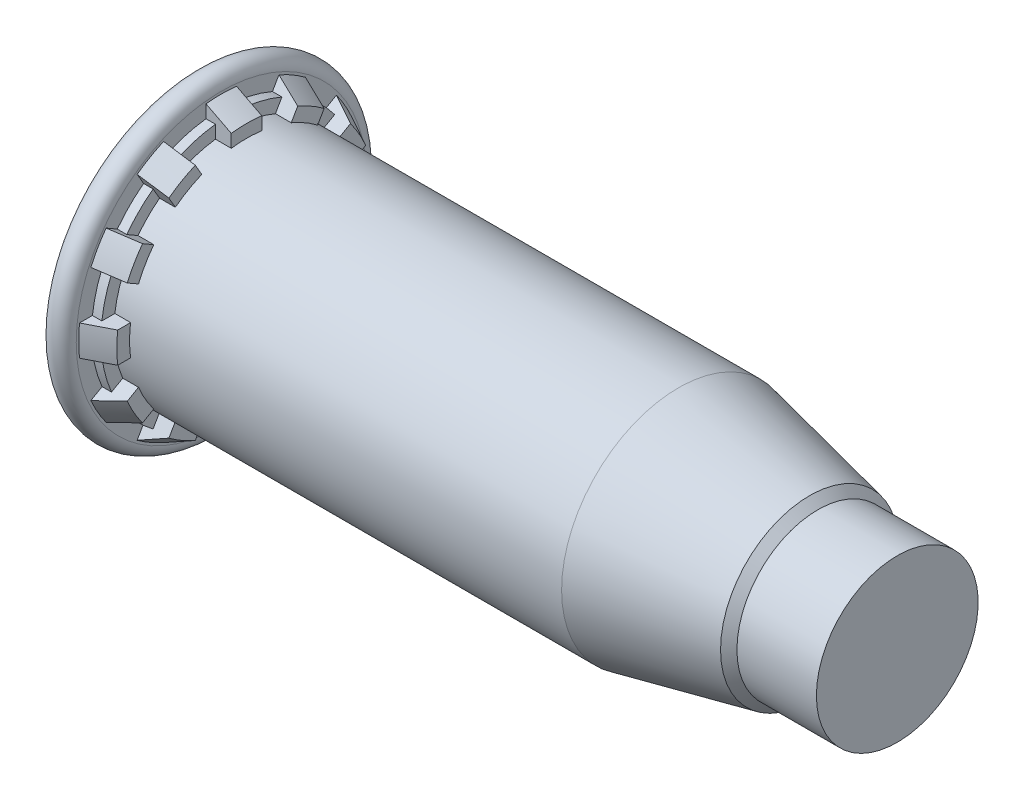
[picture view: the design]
ISO-10303-21;
HEADER;
FILE_DESCRIPTION(('STEP AP214'),'2;1');
FILE_NAME('part.step','',(''),(''),'','','');
FILE_SCHEMA(('AUTOMOTIVE_DESIGN { 1 0 10303 214 1 1 1 1 }'));
ENDSEC;
DATA;
#1=APPLICATION_CONTEXT('core data for automotive mechanical design processes');
#2=APPLICATION_PROTOCOL_DEFINITION('international standard','automotive_design',2000,#1);
#3=PRODUCT_CONTEXT('',#1,'mechanical');
#4=PRODUCT('Part','Part','',(#3));
#5=PRODUCT_RELATED_PRODUCT_CATEGORY('part','',(#4));
#6=PRODUCT_DEFINITION_FORMATION('','',#4);
#7=PRODUCT_DEFINITION_CONTEXT('part definition',#1,'design');
#8=PRODUCT_DEFINITION('design','',#6,#7);
#9=PRODUCT_DEFINITION_SHAPE('','',#8);
#10=(LENGTH_UNIT() NAMED_UNIT(*) SI_UNIT(.MILLI.,.METRE.));
#11=(NAMED_UNIT(*) PLANE_ANGLE_UNIT() SI_UNIT($,.RADIAN.));
#12=(NAMED_UNIT(*) SI_UNIT($,.STERADIAN.) SOLID_ANGLE_UNIT());
#13=UNCERTAINTY_MEASURE_WITH_UNIT(LENGTH_MEASURE(1.E-05),#10,'distance_accuracy_value','');
#14=(GEOMETRIC_REPRESENTATION_CONTEXT(3) GLOBAL_UNCERTAINTY_ASSIGNED_CONTEXT((#13)) GLOBAL_UNIT_ASSIGNED_CONTEXT((#10,
#11,#12)) REPRESENTATION_CONTEXT('',''));
#15=CARTESIAN_POINT('',(0.,0.,0.));
#16=DIRECTION('',(0.,0.,1.));
#17=DIRECTION('',(1.,0.,0.));
#18=AXIS2_PLACEMENT_3D('',#15,#16,#17);
#19=CARTESIAN_POINT('',(0.6858,0.,0.));
#20=DIRECTION('',(-1.,0.,0.));
#21=DIRECTION('',(0.,0.,1.));
#22=AXIS2_PLACEMENT_3D('',#19,#20,#21);
#23=CONICAL_SURFACE('',#22,3.8735,0.471027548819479);
#24=CARTESIAN_POINT('',(0.6858,0.,0.));
#25=DIRECTION('',(-1.,0.,0.));
#26=DIRECTION('',(0.,0.,1.));
#27=AXIS2_PLACEMENT_3D('',#24,#25,#26);
#28=CIRCLE('',#27,3.8735);
#29=CARTESIAN_POINT('',(0.6858,3.1280847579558,2.2845323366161));
#30=VERTEX_POINT('',#29);
#31=CARTESIAN_POINT('',(0.6858,3.54250541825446,1.56673469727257));
#32=VERTEX_POINT('',#31);
#33=EDGE_CURVE('E964',#30,#32,#28,.T.);
#34=ORIENTED_EDGE('',*,*,#33,.F.);
#35=CARTESIAN_POINT('',(1.3718,2.82361575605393,2.10874707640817));
#36=CARTESIAN_POINT('',(1.2288027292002,2.88712031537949,2.14541145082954));
#37=CARTESIAN_POINT('',(1.08579439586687,2.95060617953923,2.1820650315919));
#38=CARTESIAN_POINT('',(0.857053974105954,3.05211343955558,2.24067027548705));
#39=CARTESIAN_POINT('',(0.771328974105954,3.09014681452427,2.26262885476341));
#40=CARTESIAN_POINT('',(0.6856,3.12817347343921,2.28458355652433));
#41=B_SPLINE_CURVE_WITH_KNOTS('',3,(#35,#36,#37,#38,#39,#40),.UNSPECIFIED.,.F.,.F.,(4,2,4),(0.,
0.482107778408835,0.771067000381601),.UNSPECIFIED.);
#42=CARTESIAN_POINT('',(1.3716,2.82370457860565,2.10879835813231));
#43=VERTEX_POINT('',#42);
#44=EDGE_CURVE('E965',#43,#30,#41,.T.);
#45=ORIENTED_EDGE('',*,*,#44,.F.);
#46=CARTESIAN_POINT('',(1.3716,0.,0.));
#47=DIRECTION('',(-1.,0.,0.));
#48=DIRECTION('',(0.,0.,1.));
#49=AXIS2_PLACEMENT_3D('',#46,#47,#48);
#50=CIRCLE('',#49,3.52425);
#51=CARTESIAN_POINT('',(1.3716,3.23812523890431,1.39100071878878));
#52=VERTEX_POINT('',#51);
#53=EDGE_CURVE('E1233',#43,#52,#50,.T.);
#54=ORIENTED_EDGE('',*,*,#53,.T.);
#55=CARTESIAN_POINT('',(0.6856,3.54259413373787,1.5667859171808));
#56=CARTESIAN_POINT('',(0.771328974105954,3.50456747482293,1.54483121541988));
#57=CARTESIAN_POINT('',(0.857053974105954,3.46653409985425,1.52287263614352));
#58=CARTESIAN_POINT('',(1.08579439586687,3.36502683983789,1.46426739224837));
#59=CARTESIAN_POINT('',(1.2288027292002,3.30154097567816,1.42761381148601));
#60=CARTESIAN_POINT('',(1.3718,3.2380364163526,1.39094943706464));
#61=B_SPLINE_CURVE_WITH_KNOTS('',3,(#55,#56,#57,#58,#59,#60),.UNSPECIFIED.,.F.,.F.,(4,2,4),(0.,
0.288959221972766,0.771067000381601),.UNSPECIFIED.);
#62=EDGE_CURVE('E849',#32,#52,#61,.T.);
#63=ORIENTED_EDGE('',*,*,#62,.F.);
#64=EDGE_LOOP('',(#34,#45,#54,#63));
#65=FACE_BOUND('',#64,.T.);
#66=ADVANCED_FACE('F33',(#65),#23,.T.);
#67=CARTESIAN_POINT('',(0.685600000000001,2.28458355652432,3.12817347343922));
#68=CARTESIAN_POINT('',(0.771328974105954,2.2626288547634,3.09014681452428));
#69=CARTESIAN_POINT('',(0.857053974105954,2.24067027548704,3.05211343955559));
#70=CARTESIAN_POINT('',(1.08579439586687,2.18206503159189,2.95060617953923));
#71=CARTESIAN_POINT('',(1.2288027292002,2.14541145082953,2.8871203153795));
#72=CARTESIAN_POINT('',(1.3718,2.10874707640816,2.82361575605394));
#73=B_SPLINE_CURVE_WITH_KNOTS('',3,(#67,#68,#69,#70,#71,#72),.UNSPECIFIED.,.F.,.F.,(4,2,4),(0.,
0.288959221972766,0.771067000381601),.UNSPECIFIED.);
#74=CARTESIAN_POINT('',(0.6858,2.28453233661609,3.1280847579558));
#75=VERTEX_POINT('',#74);
#76=CARTESIAN_POINT('',(1.3716,2.1087983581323,2.82370457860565));
#77=VERTEX_POINT('',#76);
#78=EDGE_CURVE('E1274',#75,#77,#73,.T.);
#79=ORIENTED_EDGE('',*,*,#78,.F.);
#80=CARTESIAN_POINT('',(0.6858,1.56673469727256,3.54250541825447));
#81=VERTEX_POINT('',#80);
#82=EDGE_CURVE('E495',#81,#75,#28,.T.);
#83=ORIENTED_EDGE('',*,*,#82,.F.);
#84=CARTESIAN_POINT('',(1.3718,1.39094943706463,3.2380364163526));
#85=CARTESIAN_POINT('',(1.2288027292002,1.427613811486,3.30154097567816));
#86=CARTESIAN_POINT('',(1.08579439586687,1.46426739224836,3.3650268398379));
#87=CARTESIAN_POINT('',(0.857053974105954,1.52287263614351,3.46653409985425));
#88=CARTESIAN_POINT('',(0.771328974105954,1.54483121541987,3.50456747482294));
#89=CARTESIAN_POINT('',(0.6856,1.56678591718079,3.54259413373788));
#90=B_SPLINE_CURVE_WITH_KNOTS('',3,(#84,#85,#86,#87,#88,#89),.UNSPECIFIED.,.F.,.F.,(4,2,4),(0.,
0.482107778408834,0.7710670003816),.UNSPECIFIED.);
#91=CARTESIAN_POINT('',(1.3716,1.39100071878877,3.23812523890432));
#92=VERTEX_POINT('',#91);
#93=EDGE_CURVE('E1014',#92,#81,#90,.T.);
#94=ORIENTED_EDGE('',*,*,#93,.F.);
#95=EDGE_CURVE('E1238',#92,#77,#50,.T.);
#96=ORIENTED_EDGE('',*,*,#95,.T.);
#97=EDGE_LOOP('',(#79,#83,#94,#96));
#98=FACE_BOUND('',#97,.T.);
#99=ADVANCED_FACE('F954',(#98),#23,.T.);
#100=CARTESIAN_POINT('',(-0.377436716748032,0.414420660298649,4.39546983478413));
#101=CARTESIAN_POINT('',(-0.301617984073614,0.414420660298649,4.35668692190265));
#102=CARTESIAN_POINT('',(-0.225800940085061,0.41442066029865,4.31790070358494));
#103=CARTESIAN_POINT('',(0.339839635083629,0.414420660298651,4.02849689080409));
#104=CARTESIAN_POINT('',(0.829584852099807,0.414420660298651,3.77772613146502));
#105=CARTESIAN_POINT('',(1.56398788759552,0.414420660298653,3.40115094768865));
#106=CARTESIAN_POINT('',(1.8087531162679,0.414420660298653,3.27555603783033));
#107=CARTESIAN_POINT('',(2.29817805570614,0.414420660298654,3.02416066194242));
#108=CARTESIAN_POINT('',(2.54283776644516,0.414420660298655,2.89836019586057));
#109=CARTESIAN_POINT('',(2.78742770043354,0.414420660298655,2.77242404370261));
#110=B_SPLINE_CURVE_WITH_KNOTS('',3,(#100,#101,#102,#103,#104,#105,#106,#107,#108,#109),
.UNSPECIFIED.,.F.,.F.,(4,2,2,2,4),(0.,0.25548650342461,1.90613072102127,2.73145293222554,
3.55677535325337),.UNSPECIFIED.);
#111=CARTESIAN_POINT('',(0.6858,0.414420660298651,3.85126703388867));
#112=VERTEX_POINT('',#111);
#113=CARTESIAN_POINT('',(1.3716,0.414420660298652,3.49979907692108));
#114=VERTEX_POINT('',#113);
#115=EDGE_CURVE('E1010',#112,#114,#110,.T.);
#116=ORIENTED_EDGE('',*,*,#115,.F.);
#117=CARTESIAN_POINT('',(0.6858,-0.414420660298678,3.85126703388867));
#118=VERTEX_POINT('',#117);
#119=EDGE_CURVE('E971',#118,#112,#28,.T.);
#120=ORIENTED_EDGE('',*,*,#119,.F.);
#121=CARTESIAN_POINT('',(2.78742770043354,-0.414420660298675,2.7724240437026));
#122=CARTESIAN_POINT('',(2.54283776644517,-0.414420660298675,2.89836019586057));
#123=CARTESIAN_POINT('',(2.29817805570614,-0.414420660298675,3.02416066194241));
#124=CARTESIAN_POINT('',(1.8087531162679,-0.414420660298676,3.27555603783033));
#125=CARTESIAN_POINT('',(1.56398788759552,-0.414420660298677,3.40115094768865));
#126=CARTESIAN_POINT('',(0.829584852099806,-0.414420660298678,3.77772613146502));
#127=CARTESIAN_POINT('',(0.339839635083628,-0.414420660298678,4.02849689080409));
#128=CARTESIAN_POINT('',(-0.225800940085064,-0.41442066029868,4.31790070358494));
#129=CARTESIAN_POINT('',(-0.301617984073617,-0.41442066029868,4.35668692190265));
#130=CARTESIAN_POINT('',(-0.377436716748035,-0.41442066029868,4.39546983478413));
#131=B_SPLINE_CURVE_WITH_KNOTS('',3,(#121,#122,#123,#124,#125,#126,#127,#128,#129,#130),
.UNSPECIFIED.,.F.,.F.,(4,2,2,2,4),(0.,0.825322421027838,1.65064463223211,3.30128884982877,
3.55677535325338),.UNSPECIFIED.);
#132=CARTESIAN_POINT('',(1.3716,-0.414420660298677,3.49979907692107));
#133=VERTEX_POINT('',#132);
#134=EDGE_CURVE('E1008',#133,#118,#131,.T.);
#135=ORIENTED_EDGE('',*,*,#134,.F.);
#136=EDGE_CURVE('E1011',#133,#114,#50,.T.);
#137=ORIENTED_EDGE('',*,*,#136,.T.);
#138=EDGE_LOOP('',(#116,#120,#135,#137));
#139=FACE_BOUND('',#138,.T.);
#140=ADVANCED_FACE('F959',(#139),#23,.T.);
#141=CARTESIAN_POINT('',(0.6856,-1.56678591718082,3.54259413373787));
#142=CARTESIAN_POINT('',(0.771328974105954,-1.54483121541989,3.50456747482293));
#143=CARTESIAN_POINT('',(0.857053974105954,-1.52287263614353,3.46653409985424));
#144=CARTESIAN_POINT('',(1.08579439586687,-1.46426739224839,3.36502683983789));
#145=CARTESIAN_POINT('',(1.2288027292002,-1.42761381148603,3.30154097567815));
#146=CARTESIAN_POINT('',(1.3718,-1.39094943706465,3.2380364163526));
#147=B_SPLINE_CURVE_WITH_KNOTS('',3,(#141,#142,#143,#144,#145,#146),.UNSPECIFIED.,.F.,.F.,(4,2,
4),(0.,0.288959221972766,0.771067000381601),.UNSPECIFIED.);
#148=CARTESIAN_POINT('',(0.6858,-1.56673469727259,3.54250541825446));
#149=VERTEX_POINT('',#148);
#150=CARTESIAN_POINT('',(1.3716,-1.39100071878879,3.23812523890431));
#151=VERTEX_POINT('',#150);
#152=EDGE_CURVE('E1030',#149,#151,#147,.T.);
#153=ORIENTED_EDGE('',*,*,#152,.F.);
#154=CARTESIAN_POINT('',(0.6858,-2.28453233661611,3.12808475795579));
#155=VERTEX_POINT('',#154);
#156=EDGE_CURVE('E996',#155,#149,#28,.T.);
#157=ORIENTED_EDGE('',*,*,#156,.F.);
#158=CARTESIAN_POINT('',(1.3718,-2.10874707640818,2.82361575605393));
#159=CARTESIAN_POINT('',(1.2288027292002,-2.14541145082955,2.88712031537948));
#160=CARTESIAN_POINT('',(1.08579439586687,-2.18206503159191,2.95060617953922));
#161=CARTESIAN_POINT('',(0.857053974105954,-2.24067027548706,3.05211343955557));
#162=CARTESIAN_POINT('',(0.771328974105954,-2.26262885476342,3.09014681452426));
#163=CARTESIAN_POINT('',(0.6856,-2.28458355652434,3.1281734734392));
#164=B_SPLINE_CURVE_WITH_KNOTS('',3,(#158,#159,#160,#161,#162,#163),.UNSPECIFIED.,.F.,.F.,(4,2,
4),(0.,0.482107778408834,0.771067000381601),.UNSPECIFIED.);
#165=CARTESIAN_POINT('',(1.3716,-2.10879835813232,2.82370457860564));
#166=VERTEX_POINT('',#165);
#167=EDGE_CURVE('E1082',#166,#155,#164,.T.);
#168=ORIENTED_EDGE('',*,*,#167,.F.);
#169=EDGE_CURVE('E1346',#166,#151,#50,.T.);
#170=ORIENTED_EDGE('',*,*,#169,.T.);
#171=EDGE_LOOP('',(#153,#157,#168,#170));
#172=FACE_BOUND('',#171,.T.);
#173=ADVANCED_FACE('F1481',(#172),#23,.T.);
#174=CARTESIAN_POINT('',(0.6856,-3.12817347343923,2.28458355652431));
#175=CARTESIAN_POINT('',(0.771328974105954,-3.09014681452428,2.26262885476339));
#176=CARTESIAN_POINT('',(0.857053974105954,-3.0521134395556,2.24067027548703));
#177=CARTESIAN_POINT('',(1.08579439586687,-2.95060617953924,2.18206503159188));
#178=CARTESIAN_POINT('',(1.2288027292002,-2.88712031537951,2.14541145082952));
#179=CARTESIAN_POINT('',(1.3718,-2.82361575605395,2.10874707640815));
#180=B_SPLINE_CURVE_WITH_KNOTS('',3,(#174,#175,#176,#177,#178,#179),.UNSPECIFIED.,.F.,.F.,(4,2,
4),(0.,0.288959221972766,0.7710670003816),.UNSPECIFIED.);
#181=CARTESIAN_POINT('',(0.6858,-3.12808475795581,2.28453233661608));
#182=VERTEX_POINT('',#181);
#183=CARTESIAN_POINT('',(1.3716,-2.82370457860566,2.10879835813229));
#184=VERTEX_POINT('',#183);
#185=EDGE_CURVE('E1076',#182,#184,#180,.T.);
#186=ORIENTED_EDGE('',*,*,#185,.F.);
#187=CARTESIAN_POINT('',(0.6858,-3.54250541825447,1.56673469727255));
#188=VERTEX_POINT('',#187);
#189=EDGE_CURVE('E993',#188,#182,#28,.T.);
#190=ORIENTED_EDGE('',*,*,#189,.F.);
#191=CARTESIAN_POINT('',(1.3718,-3.23803641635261,1.39094943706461));
#192=CARTESIAN_POINT('',(1.2288027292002,-3.30154097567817,1.42761381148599));
#193=CARTESIAN_POINT('',(1.08579439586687,-3.3650268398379,1.46426739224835));
#194=CARTESIAN_POINT('',(0.857053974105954,-3.46653409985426,1.52287263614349));
#195=CARTESIAN_POINT('',(0.771328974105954,-3.50456747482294,1.54483121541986));
#196=CARTESIAN_POINT('',(0.6856,-3.54259413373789,1.56678591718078));
#197=B_SPLINE_CURVE_WITH_KNOTS('',3,(#191,#192,#193,#194,#195,#196),.UNSPECIFIED.,.F.,.F.,(4,2,
4),(0.,0.482107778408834,0.771067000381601),.UNSPECIFIED.);
#198=CARTESIAN_POINT('',(1.3716,-3.23812523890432,1.39100071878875));
#199=VERTEX_POINT('',#198);
#200=EDGE_CURVE('E1117',#199,#188,#197,.T.);
#201=ORIENTED_EDGE('',*,*,#200,.F.);
#202=EDGE_CURVE('E1341',#199,#184,#50,.T.);
#203=ORIENTED_EDGE('',*,*,#202,.T.);
#204=EDGE_LOOP('',(#186,#190,#201,#203));
#205=FACE_BOUND('',#204,.T.);
#206=ADVANCED_FACE('F1452',(#205),#23,.T.);
#207=CARTESIAN_POINT('',(-0.589165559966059,-4.50376142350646,0.414420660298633));
#208=CARTESIAN_POINT('',(-0.54848825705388,-4.48295847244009,0.414420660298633));
#209=CARTESIAN_POINT('',(-0.507811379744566,-4.46215468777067,0.414420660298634));
#210=CARTESIAN_POINT('',(0.0227243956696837,-4.19080248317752,0.414420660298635));
#211=CARTESIAN_POINT('',(0.512516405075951,-3.9401231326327,0.414420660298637));
#212=CARTESIAN_POINT('',(1.49183022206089,-3.4382371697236,0.414420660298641));
#213=CARTESIAN_POINT('',(1.98135202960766,-3.18703055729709,0.414420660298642));
#214=CARTESIAN_POINT('',(2.4706709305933,-2.93542855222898,0.414420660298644));
#215=B_SPLINE_CURVE_WITH_KNOTS('',3,(#207,#208,#209,#210,#211,#212,#213,#214),.UNSPECIFIED.,.F.,
.F.,(4,2,2,4),(0.,0.137064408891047,1.78770858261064,3.4383529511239),.UNSPECIFIED.);
#216=CARTESIAN_POINT('',(0.6858,-3.85126703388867,0.414420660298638));
#217=VERTEX_POINT('',#216);
#218=CARTESIAN_POINT('',(1.3716,-3.49979907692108,0.41442066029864));
#219=VERTEX_POINT('',#218);
#220=EDGE_CURVE('E1111',#217,#219,#215,.T.);
#221=ORIENTED_EDGE('',*,*,#220,.F.);
#222=CARTESIAN_POINT('',(0.6858,-3.85126703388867,-0.414420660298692));
#223=VERTEX_POINT('',#222);
#224=EDGE_CURVE('E990',#223,#217,#28,.T.);
#225=ORIENTED_EDGE('',*,*,#224,.F.);
#226=CARTESIAN_POINT('',(2.47067093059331,-2.93542855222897,-0.414420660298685));
#227=CARTESIAN_POINT('',(1.98135202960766,-3.18703055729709,-0.41442066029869));
#228=CARTESIAN_POINT('',(1.49183022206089,-3.4382371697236,-0.41442066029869));
#229=CARTESIAN_POINT('',(0.512516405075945,-3.9401231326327,-0.41442066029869));
#230=CARTESIAN_POINT('',(0.0227243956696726,-4.19080248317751,-0.41442066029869));
#231=CARTESIAN_POINT('',(-0.507811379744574,-4.46215468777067,-0.414420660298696));
#232=CARTESIAN_POINT('',(-0.548488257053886,-4.48295847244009,-0.414420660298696));
#233=CARTESIAN_POINT('',(-0.589165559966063,-4.50376142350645,-0.414420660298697));
#234=B_SPLINE_CURVE_WITH_KNOTS('',3,(#226,#227,#228,#229,#230,#231,#232,#233),.UNSPECIFIED.,.F.,
.F.,(4,2,2,4),(0.,1.65064436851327,3.30128854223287,3.43835295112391),.UNSPECIFIED.);
#235=CARTESIAN_POINT('',(1.3716,-3.49979907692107,-0.414420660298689));
#236=VERTEX_POINT('',#235);
#237=EDGE_CURVE('E1130',#236,#223,#234,.T.);
#238=ORIENTED_EDGE('',*,*,#237,.F.);
#239=EDGE_CURVE('E1336',#236,#219,#50,.T.);
#240=ORIENTED_EDGE('',*,*,#239,.T.);
#241=EDGE_LOOP('',(#221,#225,#238,#240));
#242=FACE_BOUND('',#241,.T.);
#243=ADVANCED_FACE('F1448',(#242),#23,.T.);
#244=CARTESIAN_POINT('',(0.6856,-3.54259413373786,-1.56678591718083));
#245=CARTESIAN_POINT('',(0.771328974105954,-3.50456747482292,-1.5448312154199));
#246=CARTESIAN_POINT('',(0.857053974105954,-3.46653409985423,-1.52287263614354));
#247=CARTESIAN_POINT('',(1.08579439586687,-3.36502683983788,-1.4642673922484));
#248=CARTESIAN_POINT('',(1.2288027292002,-3.30154097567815,-1.42761381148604));
#249=CARTESIAN_POINT('',(1.3718,-3.23803641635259,-1.39094943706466));
#250=B_SPLINE_CURVE_WITH_KNOTS('',3,(#244,#245,#246,#247,#248,#249),.UNSPECIFIED.,.F.,.F.,(4,2,
4),(0.,0.288959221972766,0.771067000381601),.UNSPECIFIED.);
#251=CARTESIAN_POINT('',(0.6858,-3.54250541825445,-1.5667346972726));
#252=VERTEX_POINT('',#251);
#253=CARTESIAN_POINT('',(1.3716,-3.2381252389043,-1.3910007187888));
#254=VERTEX_POINT('',#253);
#255=EDGE_CURVE('E1123',#252,#254,#250,.T.);
#256=ORIENTED_EDGE('',*,*,#255,.F.);
#257=CARTESIAN_POINT('',(0.6858,-3.12808475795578,-2.28453233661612));
#258=VERTEX_POINT('',#257);
#259=EDGE_CURVE('E987',#258,#252,#28,.T.);
#260=ORIENTED_EDGE('',*,*,#259,.F.);
#261=CARTESIAN_POINT('',(1.3718,-2.82361575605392,-2.10874707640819));
#262=CARTESIAN_POINT('',(1.2288027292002,-2.88712031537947,-2.14541145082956));
#263=CARTESIAN_POINT('',(1.08579439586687,-2.95060617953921,-2.18206503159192));
#264=CARTESIAN_POINT('',(0.857053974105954,-3.05211343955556,-2.24067027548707));
#265=CARTESIAN_POINT('',(0.771328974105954,-3.09014681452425,-2.26262885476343));
#266=CARTESIAN_POINT('',(0.6856,-3.12817347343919,-2.28458355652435));
#267=B_SPLINE_CURVE_WITH_KNOTS('',3,(#261,#262,#263,#264,#265,#266),.UNSPECIFIED.,.F.,.F.,(4,2,
4),(0.,0.482107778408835,0.7710670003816),.UNSPECIFIED.);
#268=CARTESIAN_POINT('',(1.3716,-2.82370457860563,-2.10879835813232));
#269=VERTEX_POINT('',#268);
#270=EDGE_CURVE('E1165',#269,#258,#267,.T.);
#271=ORIENTED_EDGE('',*,*,#270,.F.);
#272=EDGE_CURVE('E1331',#269,#254,#50,.T.);
#273=ORIENTED_EDGE('',*,*,#272,.T.);
#274=EDGE_LOOP('',(#256,#260,#271,#273));
#275=FACE_BOUND('',#274,.T.);
#276=ADVANCED_FACE('F1444',(#275),#23,.T.);
#277=CARTESIAN_POINT('',(0.6856,-2.2845835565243,-3.12817347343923));
#278=CARTESIAN_POINT('',(0.771328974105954,-2.26262885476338,-3.09014681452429));
#279=CARTESIAN_POINT('',(0.857053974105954,-2.24067027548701,-3.0521134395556));
#280=CARTESIAN_POINT('',(1.08579439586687,-2.18206503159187,-2.95060617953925));
#281=CARTESIAN_POINT('',(1.2288027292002,-2.14541145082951,-2.88712031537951));
#282=CARTESIAN_POINT('',(1.3718,-2.10874707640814,-2.82361575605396));
#283=B_SPLINE_CURVE_WITH_KNOTS('',3,(#277,#278,#279,#280,#281,#282),.UNSPECIFIED.,.F.,.F.,(4,2,
4),(0.,0.288959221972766,0.771067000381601),.UNSPECIFIED.);
#284=CARTESIAN_POINT('',(0.6858,-2.28453233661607,-3.12808475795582));
#285=VERTEX_POINT('',#284);
#286=CARTESIAN_POINT('',(1.3716,-2.10879835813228,-2.82370457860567));
#287=VERTEX_POINT('',#286);
#288=EDGE_CURVE('E1159',#285,#287,#283,.T.);
#289=ORIENTED_EDGE('',*,*,#288,.F.);
#290=CARTESIAN_POINT('',(0.6858,-1.56673469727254,-3.54250541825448));
#291=VERTEX_POINT('',#290);
#292=EDGE_CURVE('E984',#291,#285,#28,.T.);
#293=ORIENTED_EDGE('',*,*,#292,.F.);
#294=CARTESIAN_POINT('',(1.3718,-1.3909494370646,-3.23803641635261));
#295=CARTESIAN_POINT('',(1.2288027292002,-1.42761381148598,-3.30154097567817));
#296=CARTESIAN_POINT('',(1.08579439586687,-1.46426739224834,-3.36502683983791));
#297=CARTESIAN_POINT('',(0.857053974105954,-1.52287263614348,-3.46653409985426));
#298=CARTESIAN_POINT('',(0.771328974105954,-1.54483121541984,-3.50456747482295));
#299=CARTESIAN_POINT('',(0.6856,-1.56678591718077,-3.54259413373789));
#300=B_SPLINE_CURVE_WITH_KNOTS('',3,(#294,#295,#296,#297,#298,#299),.UNSPECIFIED.,.F.,.F.,(4,2,
4),(0.,0.482107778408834,0.771067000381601),.UNSPECIFIED.);
#301=CARTESIAN_POINT('',(1.3716,-1.39100071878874,-3.23812523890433));
#302=VERTEX_POINT('',#301);
#303=EDGE_CURVE('E1178',#302,#291,#300,.T.);
#304=ORIENTED_EDGE('',*,*,#303,.F.);
#305=EDGE_CURVE('E1329',#302,#287,#50,.T.);
#306=ORIENTED_EDGE('',*,*,#305,.T.);
#307=EDGE_LOOP('',(#289,#293,#304,#306));
#308=FACE_BOUND('',#307,.T.);
#309=ADVANCED_FACE('F1425',(#308),#23,.T.);
#310=CARTESIAN_POINT('',(-0.589165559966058,-0.414420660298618,-4.50376142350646));
#311=CARTESIAN_POINT('',(-0.548488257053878,-0.414420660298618,-4.48295847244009));
#312=CARTESIAN_POINT('',(-0.507811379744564,-0.414420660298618,-4.46215468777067));
#313=CARTESIAN_POINT('',(0.0227243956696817,-0.414420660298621,-4.19080248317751));
#314=CARTESIAN_POINT('',(0.51251640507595,-0.414420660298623,-3.9401231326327));
#315=CARTESIAN_POINT('',(1.49183022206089,-0.414420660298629,-3.4382371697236));
#316=CARTESIAN_POINT('',(1.98135202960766,-0.414420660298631,-3.1870305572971));
#317=CARTESIAN_POINT('',(2.4706709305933,-0.414420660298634,-2.93542855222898));
#318=B_SPLINE_CURVE_WITH_KNOTS('',3,(#310,#311,#312,#313,#314,#315,#316,#317),.UNSPECIFIED.,.F.,
.F.,(4,2,2,4),(0.,0.137064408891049,1.78770858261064,3.43835295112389),.UNSPECIFIED.);
#319=CARTESIAN_POINT('',(0.6858,-0.414420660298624,-3.85126703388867));
#320=VERTEX_POINT('',#319);
#321=CARTESIAN_POINT('',(1.3716,-0.414420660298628,-3.49979907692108));
#322=VERTEX_POINT('',#321);
#323=EDGE_CURVE('E1171',#320,#322,#318,.T.);
#324=ORIENTED_EDGE('',*,*,#323,.F.);
#325=CARTESIAN_POINT('',(0.6858,0.414420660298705,-3.85126703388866));
#326=VERTEX_POINT('',#325);
#327=EDGE_CURVE('E981',#326,#320,#28,.T.);
#328=ORIENTED_EDGE('',*,*,#327,.F.);
#329=CARTESIAN_POINT('',(2.47067093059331,0.414420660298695,-2.93542855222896));
#330=CARTESIAN_POINT('',(1.98135202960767,0.414420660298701,-3.18703055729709));
#331=CARTESIAN_POINT('',(1.49183022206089,0.414420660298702,-3.43823716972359));
#332=CARTESIAN_POINT('',(0.512516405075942,0.414420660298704,-3.9401231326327));
#333=CARTESIAN_POINT('',(0.0227243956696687,0.414420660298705,-4.19080248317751));
#334=CARTESIAN_POINT('',(-0.507811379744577,0.414420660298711,-4.46215468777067));
#335=CARTESIAN_POINT('',(-0.548488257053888,0.414420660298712,-4.48295847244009));
#336=CARTESIAN_POINT('',(-0.589165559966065,0.414420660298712,-4.50376142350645));
#337=B_SPLINE_CURVE_WITH_KNOTS('',3,(#329,#330,#331,#332,#333,#334,#335,#336),.UNSPECIFIED.,.F.,
.F.,(4,2,2,4),(0.,1.65064436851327,3.30128854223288,3.43835295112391),.UNSPECIFIED.);
#338=CARTESIAN_POINT('',(1.3716,0.414420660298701,-3.49979907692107));
#339=VERTEX_POINT('',#338);
#340=EDGE_CURVE('E1210',#339,#326,#337,.T.);
#341=ORIENTED_EDGE('',*,*,#340,.F.);
#342=EDGE_CURVE('E1236',#339,#322,#50,.T.);
#343=ORIENTED_EDGE('',*,*,#342,.T.);
#344=EDGE_LOOP('',(#324,#328,#341,#343));
#345=FACE_BOUND('',#344,.T.);
#346=ADVANCED_FACE('F1436',(#345),#23,.T.);
#347=CARTESIAN_POINT('',(0.6856,1.56678591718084,-3.54259413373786));
#348=CARTESIAN_POINT('',(0.771328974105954,1.54483121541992,-3.50456747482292));
#349=CARTESIAN_POINT('',(0.857053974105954,1.52287263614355,-3.46653409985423));
#350=CARTESIAN_POINT('',(1.08579439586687,1.46426739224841,-3.36502683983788));
#351=CARTESIAN_POINT('',(1.2288027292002,1.42761381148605,-3.30154097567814));
#352=CARTESIAN_POINT('',(1.3718,1.39094943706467,-3.23803641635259));
#353=B_SPLINE_CURVE_WITH_KNOTS('',3,(#347,#348,#349,#350,#351,#352),.UNSPECIFIED.,.F.,.F.,(4,2,
4),(0.,0.288959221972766,0.771067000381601),.UNSPECIFIED.);
#354=CARTESIAN_POINT('',(0.6858,1.56673469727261,-3.54250541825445));
#355=VERTEX_POINT('',#354);
#356=CARTESIAN_POINT('',(1.3716,1.39100071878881,-3.2381252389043));
#357=VERTEX_POINT('',#356);
#358=EDGE_CURVE('E1205',#355,#357,#353,.T.);
#359=ORIENTED_EDGE('',*,*,#358,.F.);
#360=CARTESIAN_POINT('',(0.6858,2.28453233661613,-3.12808475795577));
#361=VERTEX_POINT('',#360);
#362=EDGE_CURVE('E973',#361,#355,#28,.T.);
#363=ORIENTED_EDGE('',*,*,#362,.F.);
#364=CARTESIAN_POINT('',(1.3718,2.1087470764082,-2.82361575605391));
#365=CARTESIAN_POINT('',(1.2288027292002,2.14541145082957,-2.88712031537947));
#366=CARTESIAN_POINT('',(1.08579439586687,2.18206503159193,-2.9506061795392));
#367=CARTESIAN_POINT('',(0.857053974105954,2.24067027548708,-3.05211343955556));
#368=CARTESIAN_POINT('',(0.771328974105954,2.26262885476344,-3.09014681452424));
#369=CARTESIAN_POINT('',(0.6856,2.28458355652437,-3.12817347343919));
#370=B_SPLINE_CURVE_WITH_KNOTS('',3,(#364,#365,#366,#367,#368,#369),.UNSPECIFIED.,.F.,.F.,(4,2,
4),(0.,0.482107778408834,0.771067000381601),.UNSPECIFIED.);
#371=CARTESIAN_POINT('',(1.3716,2.10879835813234,-2.82370457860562));
#372=VERTEX_POINT('',#371);
#373=EDGE_CURVE('E656',#372,#361,#370,.T.);
#374=ORIENTED_EDGE('',*,*,#373,.F.);
#375=EDGE_CURVE('E1232',#372,#357,#50,.T.);
#376=ORIENTED_EDGE('',*,*,#375,.T.);
#377=EDGE_LOOP('',(#359,#363,#374,#376));
#378=FACE_BOUND('',#377,.T.);
#379=ADVANCED_FACE('F1438',(#378),#23,.T.);
#380=CARTESIAN_POINT('',(0.6858,3.85126703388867,0.414420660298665));
#381=VERTEX_POINT('',#380);
#382=CARTESIAN_POINT('',(0.6858,3.85126703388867,-0.414420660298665));
#383=VERTEX_POINT('',#382);
#384=EDGE_CURVE('E968',#381,#383,#28,.T.);
#385=ORIENTED_EDGE('',*,*,#384,.F.);
#386=CARTESIAN_POINT('',(2.78742770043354,2.7724240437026,0.414420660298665));
#387=CARTESIAN_POINT('',(2.54283776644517,2.89836019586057,0.414420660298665));
#388=CARTESIAN_POINT('',(2.29817805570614,3.02416066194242,0.414420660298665));
#389=CARTESIAN_POINT('',(1.8087531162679,3.27555603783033,0.414420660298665));
#390=CARTESIAN_POINT('',(1.56398788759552,3.40115094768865,0.414420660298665));
#391=CARTESIAN_POINT('',(0.829584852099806,3.77772613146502,0.414420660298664));
#392=CARTESIAN_POINT('',(0.339839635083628,4.0284968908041,0.414420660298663));
#393=CARTESIAN_POINT('',(-0.225800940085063,4.31790070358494,0.414420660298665));
#394=CARTESIAN_POINT('',(-0.301617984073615,4.35668692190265,0.414420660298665));
#395=CARTESIAN_POINT('',(-0.377436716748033,4.39546983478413,0.414420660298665));
#396=B_SPLINE_CURVE_WITH_KNOTS('',3,(#386,#387,#388,#389,#390,#391,#392,#393,#394,#395),
.UNSPECIFIED.,.F.,.F.,(4,2,2,2,4),(0.,0.825322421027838,1.65064463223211,3.30128884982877,
3.55677535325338),.UNSPECIFIED.);
#397=CARTESIAN_POINT('',(1.3716,3.49979907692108,0.414420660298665));
#398=VERTEX_POINT('',#397);
#399=EDGE_CURVE('E858',#398,#381,#396,.T.);
#400=ORIENTED_EDGE('',*,*,#399,.F.);
#401=CARTESIAN_POINT('',(1.3716,3.49979907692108,-0.414420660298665));
#402=VERTEX_POINT('',#401);
#403=EDGE_CURVE('E1234',#398,#402,#50,.T.);
#404=ORIENTED_EDGE('',*,*,#403,.T.);
#405=CARTESIAN_POINT('',(-0.377436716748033,4.39546983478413,-0.414420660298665));
#406=CARTESIAN_POINT('',(-0.301617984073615,4.35668692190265,-0.414420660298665));
#407=CARTESIAN_POINT('',(-0.225800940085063,4.31790070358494,-0.414420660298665));
#408=CARTESIAN_POINT('',(0.339839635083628,4.0284968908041,-0.414420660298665));
#409=CARTESIAN_POINT('',(0.829584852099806,3.77772613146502,-0.414420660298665));
#410=CARTESIAN_POINT('',(1.56398788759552,3.40115094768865,-0.414420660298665));
#411=CARTESIAN_POINT('',(1.8087531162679,3.27555603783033,-0.414420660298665));
#412=CARTESIAN_POINT('',(2.29817805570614,3.02416066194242,-0.414420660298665));
#413=CARTESIAN_POINT('',(2.54283776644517,2.89836019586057,-0.414420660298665));
#414=CARTESIAN_POINT('',(2.78742770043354,2.7724240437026,-0.414420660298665));
#415=B_SPLINE_CURVE_WITH_KNOTS('',3,(#405,#406,#407,#408,#409,#410,#411,#412,#413,#414),
.UNSPECIFIED.,.F.,.F.,(4,2,2,2,4),(0.,0.255486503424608,1.90613072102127,2.73145293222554,
3.55677535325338),.UNSPECIFIED.);
#416=EDGE_CURVE('E901',#383,#402,#415,.T.);
#417=ORIENTED_EDGE('',*,*,#416,.F.);
#418=EDGE_LOOP('',(#385,#400,#404,#417));
#419=FACE_BOUND('',#418,.T.);
#420=ADVANCED_FACE('F945',(#419),#23,.T.);
#421=CARTESIAN_POINT('',(1.3716,3.52425,0.));
#422=DIRECTION('',(1.,0.,0.));
#423=DIRECTION('',(0.,0.,-1.));
#424=AXIS2_PLACEMENT_3D('',#421,#422,#423);
#425=PLANE('',#424);
#426=DIRECTION('',(0.,-0.499999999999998,-0.86602540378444));
#427=VECTOR('',#426,1.);
#428=CARTESIAN_POINT('',(1.3716,1.93281753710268,2.51889685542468));
#429=LINE('',#428,#427);
#430=CARTESIAN_POINT('',(1.3716,1.93281753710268,2.51889685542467));
#431=VERTEX_POINT('',#430);
#432=EDGE_CURVE('E647',#77,#431,#429,.T.);
#433=ORIENTED_EDGE('',*,*,#432,.F.);
#434=ORIENTED_EDGE('',*,*,#95,.F.);
#435=DIRECTION('',(0.,0.499999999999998,0.86602540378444));
#436=VECTOR('',#435,1.);
#437=CARTESIAN_POINT('',(1.3716,1.21501989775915,2.93331751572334));
#438=LINE('',#437,#436);
#439=CARTESIAN_POINT('',(1.3716,1.21501989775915,2.93331751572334));
#440=VERTEX_POINT('',#439);
#441=EDGE_CURVE('E668',#440,#92,#438,.T.);
#442=ORIENTED_EDGE('',*,*,#441,.F.);
#443=CARTESIAN_POINT('',(1.3716,0.,0.));
#444=DIRECTION('',(-1.,0.,0.));
#445=DIRECTION('',(0.,0.,1.));
#446=AXIS2_PLACEMENT_3D('',#443,#444,#445);
#447=CIRCLE('',#446,3.175);
#448=EDGE_CURVE('E1250',#440,#431,#447,.T.);
#449=ORIENTED_EDGE('',*,*,#448,.T.);
#450=EDGE_LOOP('',(#433,#434,#442,#449));
#451=FACE_BOUND('',#450,.T.);
#452=ADVANCED_FACE('F939',(#451),#425,.T.);
#453=DIRECTION('',(0.,0.,-1.));
#454=VECTOR('',#453,1.);
#455=CARTESIAN_POINT('',(1.3716,0.414420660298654,3.14783743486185));
#456=LINE('',#455,#454);
#457=CARTESIAN_POINT('',(1.3716,0.414420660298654,3.14783743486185));
#458=VERTEX_POINT('',#457);
#459=EDGE_CURVE('E662',#114,#458,#456,.T.);
#460=ORIENTED_EDGE('',*,*,#459,.F.);
#461=ORIENTED_EDGE('',*,*,#136,.F.);
#462=DIRECTION('',(0.,0.,1.));
#463=VECTOR('',#462,1.);
#464=CARTESIAN_POINT('',(1.3716,-0.414420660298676,3.14783743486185));
#465=LINE('',#464,#463);
#466=CARTESIAN_POINT('',(1.3716,-0.414420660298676,3.14783743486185));
#467=VERTEX_POINT('',#466);
#468=EDGE_CURVE('E684',#467,#133,#465,.T.);
#469=ORIENTED_EDGE('',*,*,#468,.F.);
#470=EDGE_CURVE('E1383',#467,#458,#447,.T.);
#471=ORIENTED_EDGE('',*,*,#470,.T.);
#472=EDGE_LOOP('',(#460,#461,#469,#471));
#473=FACE_BOUND('',#472,.T.);
#474=ADVANCED_FACE('F948',(#473),#425,.T.);
#475=DIRECTION('',(0.,0.500000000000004,-0.866025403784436));
#476=VECTOR('',#475,1.);
#477=CARTESIAN_POINT('',(1.3716,-1.21501989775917,2.93331751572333));
#478=LINE('',#477,#476);
#479=CARTESIAN_POINT('',(1.3716,-1.21501989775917,2.93331751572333));
#480=VERTEX_POINT('',#479);
#481=EDGE_CURVE('E678',#151,#480,#478,.T.);
#482=ORIENTED_EDGE('',*,*,#481,.F.);
#483=ORIENTED_EDGE('',*,*,#169,.F.);
#484=DIRECTION('',(0.,-0.500000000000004,0.866025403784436));
#485=VECTOR('',#484,1.);
#486=CARTESIAN_POINT('',(1.3716,-1.9328175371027,2.51889685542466));
#487=LINE('',#486,#485);
#488=CARTESIAN_POINT('',(1.3716,-1.9328175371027,2.51889685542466));
#489=VERTEX_POINT('',#488);
#490=EDGE_CURVE('E701',#489,#166,#487,.T.);
#491=ORIENTED_EDGE('',*,*,#490,.F.);
#492=EDGE_CURVE('E1385',#489,#480,#447,.T.);
#493=ORIENTED_EDGE('',*,*,#492,.T.);
#494=EDGE_LOOP('',(#482,#483,#491,#493));
#495=FACE_BOUND('',#494,.T.);
#496=ADVANCED_FACE('F1482',(#495),#425,.T.);
#497=DIRECTION('',(0.,0.866025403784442,-0.499999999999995));
#498=VECTOR('',#497,1.);
#499=CARTESIAN_POINT('',(1.3716,-2.51889685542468,1.93281753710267));
#500=LINE('',#499,#498);
#501=CARTESIAN_POINT('',(1.3716,-2.51889685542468,1.93281753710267));
#502=VERTEX_POINT('',#501);
#503=EDGE_CURVE('E695',#184,#502,#500,.T.);
#504=ORIENTED_EDGE('',*,*,#503,.F.);
#505=ORIENTED_EDGE('',*,*,#202,.F.);
#506=DIRECTION('',(0.,-0.866025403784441,0.499999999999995));
#507=VECTOR('',#506,1.);
#508=CARTESIAN_POINT('',(1.3716,-2.93331751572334,1.21501989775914));
#509=LINE('',#508,#507);
#510=CARTESIAN_POINT('',(1.3716,-2.93331751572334,1.21501989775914));
#511=VERTEX_POINT('',#510);
#512=EDGE_CURVE('E718',#511,#199,#509,.T.);
#513=ORIENTED_EDGE('',*,*,#512,.F.);
#514=EDGE_CURVE('E1389',#511,#502,#447,.T.);
#515=ORIENTED_EDGE('',*,*,#514,.T.);
#516=EDGE_LOOP('',(#504,#505,#513,#515));
#517=FACE_BOUND('',#516,.T.);
#518=ADVANCED_FACE('F1471',(#517),#425,.T.);
#519=DIRECTION('',(0.,1.,0.));
#520=VECTOR('',#519,1.);
#521=CARTESIAN_POINT('',(1.3716,-3.14783743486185,0.414420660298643));
#522=LINE('',#521,#520);
#523=CARTESIAN_POINT('',(1.3716,-3.14783743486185,0.414420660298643));
#524=VERTEX_POINT('',#523);
#525=EDGE_CURVE('E712',#219,#524,#522,.T.);
#526=ORIENTED_EDGE('',*,*,#525,.F.);
#527=ORIENTED_EDGE('',*,*,#239,.F.);
#528=DIRECTION('',(0.,-1.,0.));
#529=VECTOR('',#528,1.);
#530=CARTESIAN_POINT('',(1.3716,-3.14783743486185,-0.414420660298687));
#531=LINE('',#530,#529);
#532=CARTESIAN_POINT('',(1.3716,-3.14783743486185,-0.414420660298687));
#533=VERTEX_POINT('',#532);
#534=EDGE_CURVE('E735',#533,#236,#531,.T.);
#535=ORIENTED_EDGE('',*,*,#534,.F.);
#536=EDGE_CURVE('E1395',#533,#524,#447,.T.);
#537=ORIENTED_EDGE('',*,*,#536,.T.);
#538=EDGE_LOOP('',(#526,#527,#535,#537));
#539=FACE_BOUND('',#538,.T.);
#540=ADVANCED_FACE('F1460',(#539),#425,.T.);
#541=DIRECTION('',(0.,0.866025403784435,0.500000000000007));
#542=VECTOR('',#541,1.);
#543=CARTESIAN_POINT('',(1.3716,-2.93331751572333,-1.21501989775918));
#544=LINE('',#543,#542);
#545=CARTESIAN_POINT('',(1.3716,-2.93331751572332,-1.21501989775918));
#546=VERTEX_POINT('',#545);
#547=EDGE_CURVE('E729',#254,#546,#544,.T.);
#548=ORIENTED_EDGE('',*,*,#547,.F.);
#549=ORIENTED_EDGE('',*,*,#272,.F.);
#550=DIRECTION('',(0.,-0.866025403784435,-0.500000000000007));
#551=VECTOR('',#550,1.);
#552=CARTESIAN_POINT('',(1.3716,-2.51889685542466,-1.93281753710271));
#553=LINE('',#552,#551);
#554=CARTESIAN_POINT('',(1.3716,-2.51889685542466,-1.93281753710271));
#555=VERTEX_POINT('',#554);
#556=EDGE_CURVE('E752',#555,#269,#553,.T.);
#557=ORIENTED_EDGE('',*,*,#556,.F.);
#558=EDGE_CURVE('E1401',#555,#546,#447,.T.);
#559=ORIENTED_EDGE('',*,*,#558,.T.);
#560=EDGE_LOOP('',(#548,#549,#557,#559));
#561=FACE_BOUND('',#560,.T.);
#562=ADVANCED_FACE('F1576',(#561),#425,.T.);
#563=DIRECTION('',(0.,0.499999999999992,0.866025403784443));
#564=VECTOR('',#563,1.);
#565=CARTESIAN_POINT('',(1.3716,-1.93281753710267,-2.51889685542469));
#566=LINE('',#565,#564);
#567=CARTESIAN_POINT('',(1.3716,-1.93281753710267,-2.51889685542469));
#568=VERTEX_POINT('',#567);
#569=EDGE_CURVE('E746',#287,#568,#566,.T.);
#570=ORIENTED_EDGE('',*,*,#569,.F.);
#571=ORIENTED_EDGE('',*,*,#305,.F.);
#572=DIRECTION('',(0.,-0.499999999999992,-0.866025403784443));
#573=VECTOR('',#572,1.);
#574=CARTESIAN_POINT('',(1.3716,-1.21501989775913,-2.93331751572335));
#575=LINE('',#574,#573);
#576=CARTESIAN_POINT('',(1.3716,-1.21501989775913,-2.93331751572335));
#577=VERTEX_POINT('',#576);
#578=EDGE_CURVE('E769',#577,#302,#575,.T.);
#579=ORIENTED_EDGE('',*,*,#578,.F.);
#580=EDGE_CURVE('E1407',#577,#568,#447,.T.);
#581=ORIENTED_EDGE('',*,*,#580,.T.);
#582=EDGE_LOOP('',(#570,#571,#579,#581));
#583=FACE_BOUND('',#582,.T.);
#584=ADVANCED_FACE('F1417',(#583),#425,.T.);
#585=DIRECTION('',(0.,0.,1.));
#586=VECTOR('',#585,1.);
#587=CARTESIAN_POINT('',(1.3716,-0.414420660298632,-3.14783743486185));
#588=LINE('',#587,#586);
#589=CARTESIAN_POINT('',(1.3716,-0.414420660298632,-3.14783743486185));
#590=VERTEX_POINT('',#589);
#591=EDGE_CURVE('E763',#322,#590,#588,.T.);
#592=ORIENTED_EDGE('',*,*,#591,.F.);
#593=ORIENTED_EDGE('',*,*,#342,.F.);
#594=DIRECTION('',(0.,0.,-1.));
#595=VECTOR('',#594,1.);
#596=CARTESIAN_POINT('',(1.3716,0.414420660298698,-3.14783743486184));
#597=LINE('',#596,#595);
#598=CARTESIAN_POINT('',(1.3716,0.414420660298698,-3.14783743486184));
#599=VERTEX_POINT('',#598);
#600=EDGE_CURVE('E786',#599,#339,#597,.T.);
#601=ORIENTED_EDGE('',*,*,#600,.F.);
#602=EDGE_CURVE('E1248',#599,#590,#447,.T.);
#603=ORIENTED_EDGE('',*,*,#602,.T.);
#604=EDGE_LOOP('',(#592,#593,#601,#603));
#605=FACE_BOUND('',#604,.T.);
#606=ADVANCED_FACE('F1326',(#605),#425,.T.);
#607=DIRECTION('',(0.,-0.50000000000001,0.866025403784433));
#608=VECTOR('',#607,1.);
#609=CARTESIAN_POINT('',(1.3716,1.21501989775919,-2.93331751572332));
#610=LINE('',#609,#608);
#611=CARTESIAN_POINT('',(1.3716,1.21501989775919,-2.93331751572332));
#612=VERTEX_POINT('',#611);
#613=EDGE_CURVE('E780',#357,#612,#610,.T.);
#614=ORIENTED_EDGE('',*,*,#613,.F.);
#615=ORIENTED_EDGE('',*,*,#375,.F.);
#616=DIRECTION('',(0.,0.50000000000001,-0.866025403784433));
#617=VECTOR('',#616,1.);
#618=CARTESIAN_POINT('',(1.3716,1.93281753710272,-2.51889685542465));
#619=LINE('',#618,#617);
#620=CARTESIAN_POINT('',(1.3716,1.93281753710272,-2.51889685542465));
#621=VERTEX_POINT('',#620);
#622=EDGE_CURVE('E641',#621,#372,#619,.T.);
#623=ORIENTED_EDGE('',*,*,#622,.F.);
#624=EDGE_CURVE('E1244',#621,#612,#447,.T.);
#625=ORIENTED_EDGE('',*,*,#624,.T.);
#626=EDGE_LOOP('',(#614,#615,#623,#625));
#627=FACE_BOUND('',#626,.T.);
#628=ADVANCED_FACE('F1592',(#627),#425,.T.);
#629=DIRECTION('',(0.,-0.866025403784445,0.499999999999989));
#630=VECTOR('',#629,1.);
#631=CARTESIAN_POINT('',(1.3716,2.5188968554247,-1.93281753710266));
#632=LINE('',#631,#630);
#633=CARTESIAN_POINT('',(1.3716,2.82370457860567,-2.10879835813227));
#634=VERTEX_POINT('',#633);
#635=CARTESIAN_POINT('',(1.3716,2.5188968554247,-1.93281753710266));
#636=VERTEX_POINT('',#635);
#637=EDGE_CURVE('E797',#634,#636,#632,.T.);
#638=ORIENTED_EDGE('',*,*,#637,.F.);
#639=CARTESIAN_POINT('',(1.3716,3.23812523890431,-1.39100071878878));
#640=VERTEX_POINT('',#639);
#641=EDGE_CURVE('E972',#640,#634,#50,.T.);
#642=ORIENTED_EDGE('',*,*,#641,.F.);
#643=DIRECTION('',(0.,0.866025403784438,-0.500000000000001));
#644=VECTOR('',#643,1.);
#645=CARTESIAN_POINT('',(1.3716,2.93331751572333,-1.21501989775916));
#646=LINE('',#645,#644);
#647=CARTESIAN_POINT('',(1.3716,2.93331751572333,-1.21501989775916));
#648=VERTEX_POINT('',#647);
#649=EDGE_CURVE('E875',#648,#640,#646,.T.);
#650=ORIENTED_EDGE('',*,*,#649,.F.);
#651=EDGE_CURVE('E1230',#648,#636,#447,.T.);
#652=ORIENTED_EDGE('',*,*,#651,.T.);
#653=EDGE_LOOP('',(#638,#642,#650,#652));
#654=FACE_BOUND('',#653,.T.);
#655=ADVANCED_FACE('F951',(#654),#425,.T.);
#656=DIRECTION('',(0.,0.866025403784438,0.500000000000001));
#657=VECTOR('',#656,1.);
#658=CARTESIAN_POINT('',(1.3716,2.51889685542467,1.93281753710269));
#659=LINE('',#658,#657);
#660=CARTESIAN_POINT('',(1.3716,2.51889685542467,1.93281753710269));
#661=VERTEX_POINT('',#660);
#662=EDGE_CURVE('E652',#661,#43,#659,.T.);
#663=ORIENTED_EDGE('',*,*,#662,.F.);
#664=CARTESIAN_POINT('',(1.3716,2.93331751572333,1.21501989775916));
#665=VERTEX_POINT('',#664);
#666=EDGE_CURVE('E1245',#661,#665,#447,.T.);
#667=ORIENTED_EDGE('',*,*,#666,.T.);
#668=DIRECTION('',(0.,-0.866025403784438,-0.500000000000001));
#669=VECTOR('',#668,1.);
#670=CARTESIAN_POINT('',(1.3716,2.93331751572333,1.21501989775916));
#671=LINE('',#670,#669);
#672=EDGE_CURVE('E1273',#52,#665,#671,.T.);
#673=ORIENTED_EDGE('',*,*,#672,.F.);
#674=ORIENTED_EDGE('',*,*,#53,.F.);
#675=EDGE_LOOP('',(#663,#667,#673,#674));
#676=FACE_BOUND('',#675,.T.);
#677=ADVANCED_FACE('F940',(#676),#425,.T.);
#678=CARTESIAN_POINT('',(0.,0.,0.));
#679=DIRECTION('',(-1.,0.,0.));
#680=DIRECTION('',(0.,0.,1.));
#681=AXIS2_PLACEMENT_3D('',#678,#679,#680);
#682=PLANE('',#681);
#683=CARTESIAN_POINT('',(0.,0.,0.));
#684=DIRECTION('',(-1.,0.,0.));
#685=DIRECTION('',(0.,0.,1.));
#686=AXIS2_PLACEMENT_3D('',#683,#684,#685);
#687=CIRCLE('',#686,3.93446);
#688=CARTESIAN_POINT('',(0.,0.,3.93446));
#689=VERTEX_POINT('',#688);
#690=EDGE_CURVE('E1287',#689,#689,#687,.T.);
#691=ORIENTED_EDGE('',*,*,#690,.T.);
#692=EDGE_LOOP('',(#691));
#693=FACE_BOUND('',#692,.T.);
#694=ADVANCED_FACE('F35',(#693),#682,.T.);
#695=CARTESIAN_POINT('',(0.,0.,0.));
#696=DIRECTION('',(-1.,0.,0.));
#697=DIRECTION('',(0.,0.,1.));
#698=AXIS2_PLACEMENT_3D('',#695,#696,#697);
#699=CYLINDRICAL_SURFACE('',#698,3.93446);
#700=CARTESIAN_POINT('',(0.00507999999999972,0.,0.));
#701=DIRECTION('',(-1.,0.,0.));
#702=DIRECTION('',(0.,0.,1.));
#703=AXIS2_PLACEMENT_3D('',#700,#701,#702);
#704=CIRCLE('',#703,3.93446);
#705=CARTESIAN_POINT('',(0.00507999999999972,0.,3.93446));
#706=VERTEX_POINT('',#705);
#707=EDGE_CURVE('E1292',#706,#706,#704,.T.);
#708=ORIENTED_EDGE('',*,*,#707,.T.);
#709=EDGE_LOOP('',(#708));
#710=FACE_BOUND('',#709,.T.);
#711=ORIENTED_EDGE('',*,*,#690,.F.);
#712=EDGE_LOOP('',(#711));
#713=FACE_BOUND('',#712,.T.);
#714=ADVANCED_FACE('F1614',(#710,#713),#699,.T.);
#715=CARTESIAN_POINT('',(0.00507999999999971,3.93954,0.));
#716=DIRECTION('',(1.,0.,0.));
#717=DIRECTION('',(0.,0.,-1.));
#718=AXIS2_PLACEMENT_3D('',#715,#716,#717);
#719=PLANE('',#718);
#720=ORIENTED_EDGE('',*,*,#707,.F.);
#721=EDGE_LOOP('',(#720));
#722=FACE_BOUND('',#721,.T.);
#723=CARTESIAN_POINT('',(0.0050799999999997,0.,0.));
#724=DIRECTION('',(-1.,0.,0.));
#725=DIRECTION('',(0.,0.,1.));
#726=AXIS2_PLACEMENT_3D('',#723,#724,#725);
#727=CIRCLE('',#726,3.93954);
#728=CARTESIAN_POINT('',(0.0050799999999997,0.,3.93954));
#729=VERTEX_POINT('',#728);
#730=EDGE_CURVE('E980',#729,#729,#727,.T.);
#731=ORIENTED_EDGE('',*,*,#730,.T.);
#732=EDGE_LOOP('',(#731));
#733=FACE_BOUND('',#732,.T.);
#734=ADVANCED_FACE('F1621',(#722,#733),#719,.F.);
#735=CARTESIAN_POINT('',(0.34544,0.,0.));
#736=DIRECTION('',(-1.,0.,0.));
#737=DIRECTION('',(0.,0.,1.));
#738=AXIS2_PLACEMENT_3D('',#735,#736,#737);
#739=TOROIDAL_SURFACE('',#738,3.93954,0.34036);
#740=CARTESIAN_POINT('',(0.6858,0.,0.));
#741=DIRECTION('',(-1.,0.,0.));
#742=DIRECTION('',(0.,0.,1.));
#743=AXIS2_PLACEMENT_3D('',#740,#741,#742);
#744=CIRCLE('',#743,3.93954);
#745=CARTESIAN_POINT('',(0.6858,0.,3.93954));
#746=VERTEX_POINT('',#745);
#747=EDGE_CURVE('E977',#746,#746,#744,.T.);
#748=ORIENTED_EDGE('',*,*,#747,.T.);
#749=EDGE_LOOP('',(#748));
#750=FACE_BOUND('',#749,.T.);
#751=ORIENTED_EDGE('',*,*,#730,.F.);
#752=EDGE_LOOP('',(#751));
#753=FACE_BOUND('',#752,.T.);
#754=ADVANCED_FACE('F1628',(#750,#753),#739,.T.);
#755=CARTESIAN_POINT('',(0.6858,3.93954,0.));
#756=DIRECTION('',(1.,0.,0.));
#757=DIRECTION('',(0.,0.,-1.));
#758=AXIS2_PLACEMENT_3D('',#755,#756,#757);
#759=PLANE('',#758);
#760=ORIENTED_EDGE('',*,*,#747,.F.);
#761=EDGE_LOOP('',(#760));
#762=FACE_BOUND('',#761,.T.);
#763=ORIENTED_EDGE('',*,*,#362,.T.);
#764=DIRECTION('',(0.,-0.50000000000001,0.866025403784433));
#765=VECTOR('',#764,1.);
#766=CARTESIAN_POINT('',(0.6858,1.39100071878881,-3.2381252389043));
#767=LINE('',#766,#765);
#768=CARTESIAN_POINT('',(0.6858,1.39100071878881,-3.2381252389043));
#769=VERTEX_POINT('',#768);
#770=EDGE_CURVE('E605',#355,#769,#767,.T.);
#771=ORIENTED_EDGE('',*,*,#770,.T.);
#772=CARTESIAN_POINT('',(0.6858,0.,0.));
#773=DIRECTION('',(-1.,0.,0.));
#774=DIRECTION('',(0.,-0.866025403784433,-0.50000000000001));
#775=AXIS2_PLACEMENT_3D('',#772,#773,#774);
#776=CIRCLE('',#775,3.52425);
#777=CARTESIAN_POINT('',(0.6858,0.414420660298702,-3.49979907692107));
#778=VERTEX_POINT('',#777);
#779=EDGE_CURVE('E607',#769,#778,#776,.T.);
#780=ORIENTED_EDGE('',*,*,#779,.T.);
#781=DIRECTION('',(0.,0.,-1.));
#782=VECTOR('',#781,1.);
#783=CARTESIAN_POINT('',(0.6858,0.414420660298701,-3.49979907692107));
#784=LINE('',#783,#782);
#785=EDGE_CURVE('E611',#778,#326,#784,.T.);
#786=ORIENTED_EDGE('',*,*,#785,.T.);
#787=ORIENTED_EDGE('',*,*,#327,.T.);
#788=DIRECTION('',(0.,0.,1.));
#789=VECTOR('',#788,1.);
#790=CARTESIAN_POINT('',(0.6858,-0.414420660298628,-3.49979907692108));
#791=LINE('',#790,#789);
#792=CARTESIAN_POINT('',(0.6858,-0.414420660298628,-3.49979907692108));
#793=VERTEX_POINT('',#792);
#794=EDGE_CURVE('E592',#320,#793,#791,.T.);
#795=ORIENTED_EDGE('',*,*,#794,.T.);
#796=CARTESIAN_POINT('',(0.6858,0.,0.));
#797=DIRECTION('',(-1.,0.,0.));
#798=DIRECTION('',(0.,-1.,0.));
#799=AXIS2_PLACEMENT_3D('',#796,#797,#798);
#800=CIRCLE('',#799,3.52425);
#801=CARTESIAN_POINT('',(0.6858,-1.39100071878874,-3.23812523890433));
#802=VERTEX_POINT('',#801);
#803=EDGE_CURVE('E594',#793,#802,#800,.T.);
#804=ORIENTED_EDGE('',*,*,#803,.T.);
#805=DIRECTION('',(0.,-0.499999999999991,-0.866025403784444));
#806=VECTOR('',#805,1.);
#807=CARTESIAN_POINT('',(0.6858,-1.39100071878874,-3.23812523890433));
#808=LINE('',#807,#806);
#809=EDGE_CURVE('E598',#802,#291,#808,.T.);
#810=ORIENTED_EDGE('',*,*,#809,.T.);
#811=ORIENTED_EDGE('',*,*,#292,.T.);
#812=DIRECTION('',(0.,0.499999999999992,0.866025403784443));
#813=VECTOR('',#812,1.);
#814=CARTESIAN_POINT('',(0.6858,-2.10879835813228,-2.82370457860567));
#815=LINE('',#814,#813);
#816=CARTESIAN_POINT('',(0.6858,-2.10879835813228,-2.82370457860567));
#817=VERTEX_POINT('',#816);
#818=EDGE_CURVE('E579',#285,#817,#815,.T.);
#819=ORIENTED_EDGE('',*,*,#818,.T.);
#820=CARTESIAN_POINT('',(0.6858,0.,0.));
#821=DIRECTION('',(-1.,0.,0.));
#822=DIRECTION('',(0.,-0.866025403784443,0.499999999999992));
#823=AXIS2_PLACEMENT_3D('',#820,#821,#822);
#824=CIRCLE('',#823,3.52425);
#825=CARTESIAN_POINT('',(0.6858,-2.82370457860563,-2.10879835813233));
#826=VERTEX_POINT('',#825);
#827=EDGE_CURVE('E581',#817,#826,#824,.T.);
#828=ORIENTED_EDGE('',*,*,#827,.T.);
#829=DIRECTION('',(0.,-0.866025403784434,-0.500000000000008));
#830=VECTOR('',#829,1.);
#831=CARTESIAN_POINT('',(0.6858,-2.82370457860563,-2.10879835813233));
#832=LINE('',#831,#830);
#833=EDGE_CURVE('E585',#826,#258,#832,.T.);
#834=ORIENTED_EDGE('',*,*,#833,.T.);
#835=ORIENTED_EDGE('',*,*,#259,.T.);
#836=DIRECTION('',(0.,0.866025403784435,0.500000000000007));
#837=VECTOR('',#836,1.);
#838=CARTESIAN_POINT('',(0.6858,-3.2381252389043,-1.3910007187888));
#839=LINE('',#838,#837);
#840=CARTESIAN_POINT('',(0.6858,-3.2381252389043,-1.3910007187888));
#841=VERTEX_POINT('',#840);
#842=EDGE_CURVE('E566',#252,#841,#839,.T.);
#843=ORIENTED_EDGE('',*,*,#842,.T.);
#844=CARTESIAN_POINT('',(0.6858,0.,0.));
#845=DIRECTION('',(-1.,0.,0.));
#846=DIRECTION('',(0.,-0.500000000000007,0.866025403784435));
#847=AXIS2_PLACEMENT_3D('',#844,#845,#846);
#848=CIRCLE('',#847,3.52425);
#849=CARTESIAN_POINT('',(0.6858,-3.49979907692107,-0.414420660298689));
#850=VERTEX_POINT('',#849);
#851=EDGE_CURVE('E568',#841,#850,#848,.T.);
#852=ORIENTED_EDGE('',*,*,#851,.T.);
#853=DIRECTION('',(0.,-1.,0.));
#854=VECTOR('',#853,1.);
#855=CARTESIAN_POINT('',(0.6858,-3.49979907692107,-0.414420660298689));
#856=LINE('',#855,#854);
#857=EDGE_CURVE('E572',#850,#223,#856,.T.);
#858=ORIENTED_EDGE('',*,*,#857,.T.);
#859=ORIENTED_EDGE('',*,*,#224,.T.);
#860=DIRECTION('',(0.,1.,0.));
#861=VECTOR('',#860,1.);
#862=CARTESIAN_POINT('',(0.6858,-3.49979907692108,0.41442066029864));
#863=LINE('',#862,#861);
#864=CARTESIAN_POINT('',(0.6858,-3.49979907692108,0.41442066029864));
#865=VERTEX_POINT('',#864);
#866=EDGE_CURVE('E553',#217,#865,#863,.T.);
#867=ORIENTED_EDGE('',*,*,#866,.T.);
#868=CARTESIAN_POINT('',(0.6858,0.,0.));
#869=DIRECTION('',(-1.,0.,0.));
#870=DIRECTION('',(0.,0.,1.));
#871=AXIS2_PLACEMENT_3D('',#868,#869,#870);
#872=CIRCLE('',#871,3.52425);
#873=CARTESIAN_POINT('',(0.6858,-3.23812523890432,1.39100071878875));
#874=VERTEX_POINT('',#873);
#875=EDGE_CURVE('E555',#865,#874,#872,.T.);
#876=ORIENTED_EDGE('',*,*,#875,.T.);
#877=DIRECTION('',(0.,-0.866025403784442,0.499999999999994));
#878=VECTOR('',#877,1.);
#879=CARTESIAN_POINT('',(0.6858,-3.23812523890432,1.39100071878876));
#880=LINE('',#879,#878);
#881=EDGE_CURVE('E559',#874,#188,#880,.T.);
#882=ORIENTED_EDGE('',*,*,#881,.T.);
#883=ORIENTED_EDGE('',*,*,#189,.T.);
#884=DIRECTION('',(0.,0.866025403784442,-0.499999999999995));
#885=VECTOR('',#884,1.);
#886=CARTESIAN_POINT('',(0.6858,-2.82370457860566,2.10879835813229));
#887=LINE('',#886,#885);
#888=CARTESIAN_POINT('',(0.6858,-2.82370457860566,2.10879835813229));
#889=VERTEX_POINT('',#888);
#890=EDGE_CURVE('E540',#182,#889,#887,.T.);
#891=ORIENTED_EDGE('',*,*,#890,.T.);
#892=CARTESIAN_POINT('',(0.6858,0.,0.));
#893=DIRECTION('',(-1.,0.,0.));
#894=DIRECTION('',(0.,0.499999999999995,0.866025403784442));
#895=AXIS2_PLACEMENT_3D('',#892,#893,#894);
#896=CIRCLE('',#895,3.52425);
#897=CARTESIAN_POINT('',(0.6858,-2.10879835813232,2.82370457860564));
#898=VERTEX_POINT('',#897);
#899=EDGE_CURVE('E542',#889,#898,#896,.T.);
#900=ORIENTED_EDGE('',*,*,#899,.T.);
#901=DIRECTION('',(0.,-0.500000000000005,0.866025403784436));
#902=VECTOR('',#901,1.);
#903=CARTESIAN_POINT('',(0.6858,-2.10879835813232,2.82370457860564));
#904=LINE('',#903,#902);
#905=EDGE_CURVE('E546',#898,#155,#904,.T.);
#906=ORIENTED_EDGE('',*,*,#905,.T.);
#907=ORIENTED_EDGE('',*,*,#156,.T.);
#908=DIRECTION('',(0.,0.500000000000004,-0.866025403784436));
#909=VECTOR('',#908,1.);
#910=CARTESIAN_POINT('',(0.6858,-1.39100071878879,3.23812523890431));
#911=LINE('',#910,#909);
#912=CARTESIAN_POINT('',(0.6858,-1.39100071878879,3.23812523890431));
#913=VERTEX_POINT('',#912);
#914=EDGE_CURVE('E527',#149,#913,#911,.T.);
#915=ORIENTED_EDGE('',*,*,#914,.T.);
#916=CARTESIAN_POINT('',(0.6858,0.,0.));
#917=DIRECTION('',(-1.,0.,0.));
#918=DIRECTION('',(0.,0.866025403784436,0.500000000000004));
#919=AXIS2_PLACEMENT_3D('',#916,#917,#918);
#920=CIRCLE('',#919,3.52425);
#921=CARTESIAN_POINT('',(0.6858,-0.414420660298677,3.49979907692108));
#922=VERTEX_POINT('',#921);
#923=EDGE_CURVE('E529',#913,#922,#920,.T.);
#924=ORIENTED_EDGE('',*,*,#923,.T.);
#925=DIRECTION('',(0.,0.,1.));
#926=VECTOR('',#925,1.);
#927=CARTESIAN_POINT('',(0.6858,-0.414420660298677,3.49979907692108));
#928=LINE('',#927,#926);
#929=EDGE_CURVE('E533',#922,#118,#928,.T.);
#930=ORIENTED_EDGE('',*,*,#929,.T.);
#931=ORIENTED_EDGE('',*,*,#119,.T.);
#932=DIRECTION('',(0.,0.,-1.));
#933=VECTOR('',#932,1.);
#934=CARTESIAN_POINT('',(0.6858,0.414420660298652,3.49979907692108));
#935=LINE('',#934,#933);
#936=CARTESIAN_POINT('',(0.6858,0.414420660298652,3.49979907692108));
#937=VERTEX_POINT('',#936);
#938=EDGE_CURVE('E515',#112,#937,#935,.T.);
#939=ORIENTED_EDGE('',*,*,#938,.T.);
#940=CARTESIAN_POINT('',(0.6858,0.,0.));
#941=DIRECTION('',(-1.,0.,0.));
#942=DIRECTION('',(0.,1.,0.));
#943=AXIS2_PLACEMENT_3D('',#940,#941,#942);
#944=CIRCLE('',#943,3.52425);
#945=CARTESIAN_POINT('',(0.6858,1.39100071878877,3.23812523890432));
#946=VERTEX_POINT('',#945);
#947=EDGE_CURVE('E517',#937,#946,#944,.T.);
#948=ORIENTED_EDGE('',*,*,#947,.T.);
#949=DIRECTION('',(0.,0.499999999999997,0.86602540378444));
#950=VECTOR('',#949,1.);
#951=CARTESIAN_POINT('',(0.6858,1.39100071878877,3.23812523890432));
#952=LINE('',#951,#950);
#953=EDGE_CURVE('E521',#946,#81,#952,.T.);
#954=ORIENTED_EDGE('',*,*,#953,.T.);
#955=ORIENTED_EDGE('',*,*,#82,.T.);
#956=DIRECTION('',(0.,-0.499999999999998,-0.86602540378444));
#957=VECTOR('',#956,1.);
#958=CARTESIAN_POINT('',(0.6858,2.1087983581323,2.82370457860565));
#959=LINE('',#958,#957);
#960=CARTESIAN_POINT('',(0.6858,2.1087983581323,2.82370457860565));
#961=VERTEX_POINT('',#960);
#962=EDGE_CURVE('E485',#75,#961,#959,.T.);
#963=ORIENTED_EDGE('',*,*,#962,.T.);
#964=CARTESIAN_POINT('',(0.6858,0.,0.));
#965=DIRECTION('',(-1.,0.,0.));
#966=DIRECTION('',(0.,0.86602540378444,-0.499999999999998));
#967=AXIS2_PLACEMENT_3D('',#964,#965,#966);
#968=CIRCLE('',#967,3.52425);
#969=CARTESIAN_POINT('',(0.6858,2.82370457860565,2.10879835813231));
#970=VERTEX_POINT('',#969);
#971=EDGE_CURVE('E491',#961,#970,#968,.T.);
#972=ORIENTED_EDGE('',*,*,#971,.T.);
#973=DIRECTION('',(0.,0.866025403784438,0.500000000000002));
#974=VECTOR('',#973,1.);
#975=CARTESIAN_POINT('',(0.6858,2.82370457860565,2.10879835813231));
#976=LINE('',#975,#974);
#977=EDGE_CURVE('E506',#970,#30,#976,.T.);
#978=ORIENTED_EDGE('',*,*,#977,.T.);
#979=ORIENTED_EDGE('',*,*,#33,.T.);
#980=DIRECTION('',(0.,-0.866025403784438,-0.500000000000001));
#981=VECTOR('',#980,1.);
#982=CARTESIAN_POINT('',(0.6858,3.23812523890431,1.39100071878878));
#983=LINE('',#982,#981);
#984=CARTESIAN_POINT('',(0.6858,3.23812523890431,1.39100071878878));
#985=VERTEX_POINT('',#984);
#986=EDGE_CURVE('E513',#32,#985,#983,.T.);
#987=ORIENTED_EDGE('',*,*,#986,.T.);
#988=CARTESIAN_POINT('',(0.6858,0.,0.));
#989=DIRECTION('',(-1.,0.,0.));
#990=DIRECTION('',(0.,0.500000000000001,-0.866025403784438));
#991=AXIS2_PLACEMENT_3D('',#988,#989,#990);
#992=CIRCLE('',#991,3.52425);
#993=CARTESIAN_POINT('',(0.6858,3.49979907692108,0.414420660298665));
#994=VERTEX_POINT('',#993);
#995=EDGE_CURVE('E631',#985,#994,#992,.T.);
#996=ORIENTED_EDGE('',*,*,#995,.T.);
#997=DIRECTION('',(0.,1.,0.));
#998=VECTOR('',#997,1.);
#999=CARTESIAN_POINT('',(0.6858,3.49979907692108,0.414420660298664));
#1000=LINE('',#999,#998);
#1001=EDGE_CURVE('E634',#994,#381,#1000,.T.);
#1002=ORIENTED_EDGE('',*,*,#1001,.T.);
#1003=ORIENTED_EDGE('',*,*,#384,.T.);
#1004=DIRECTION('',(0.,-1.,0.));
#1005=VECTOR('',#1004,1.);
#1006=CARTESIAN_POINT('',(0.6858,3.49979907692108,-0.414420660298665));
#1007=LINE('',#1006,#1005);
#1008=CARTESIAN_POINT('',(0.6858,3.49979907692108,-0.414420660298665));
#1009=VERTEX_POINT('',#1008);
#1010=EDGE_CURVE('E857',#383,#1009,#1007,.T.);
#1011=ORIENTED_EDGE('',*,*,#1010,.T.);
#1012=CARTESIAN_POINT('',(0.6858,0.,0.));
#1013=DIRECTION('',(-1.,0.,0.));
#1014=DIRECTION('',(0.,0.,-1.));
#1015=AXIS2_PLACEMENT_3D('',#1012,#1013,#1014);
#1016=CIRCLE('',#1015,3.52425);
#1017=CARTESIAN_POINT('',(0.6858,3.23812523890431,-1.39100071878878));
#1018=VERTEX_POINT('',#1017);
#1019=EDGE_CURVE('E865',#1009,#1018,#1016,.T.);
#1020=ORIENTED_EDGE('',*,*,#1019,.T.);
#1021=DIRECTION('',(0.,0.866025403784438,-0.5));
#1022=VECTOR('',#1021,1.);
#1023=CARTESIAN_POINT('',(0.6858,3.23812523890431,-1.39100071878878));
#1024=LINE('',#1023,#1022);
#1025=CARTESIAN_POINT('',(0.6858,3.54250541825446,-1.56673469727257));
#1026=VERTEX_POINT('',#1025);
#1027=EDGE_CURVE('E868',#1018,#1026,#1024,.T.);
#1028=ORIENTED_EDGE('',*,*,#1027,.T.);
#1029=CARTESIAN_POINT('',(0.6858,3.12808475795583,-2.28453233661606));
#1030=VERTEX_POINT('',#1029);
#1031=EDGE_CURVE('E970',#1026,#1030,#28,.T.);
#1032=ORIENTED_EDGE('',*,*,#1031,.T.);
#1033=DIRECTION('',(0.,-0.866025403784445,0.499999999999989));
#1034=VECTOR('',#1033,1.);
#1035=CARTESIAN_POINT('',(0.6858,2.82370457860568,-2.10879835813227));
#1036=LINE('',#1035,#1034);
#1037=CARTESIAN_POINT('',(0.6858,2.82370457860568,-2.10879835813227));
#1038=VERTEX_POINT('',#1037);
#1039=EDGE_CURVE('E618',#1030,#1038,#1036,.T.);
#1040=ORIENTED_EDGE('',*,*,#1039,.T.);
#1041=CARTESIAN_POINT('',(0.6858,0.,0.));
#1042=DIRECTION('',(-1.,0.,0.));
#1043=DIRECTION('',(0.,-0.499999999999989,-0.866025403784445));
#1044=AXIS2_PLACEMENT_3D('',#1041,#1042,#1043);
#1045=CIRCLE('',#1044,3.52425);
#1046=CARTESIAN_POINT('',(0.6858,2.10879835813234,-2.82370457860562));
#1047=VERTEX_POINT('',#1046);
#1048=EDGE_CURVE('E620',#1038,#1047,#1045,.T.);
#1049=ORIENTED_EDGE('',*,*,#1048,.T.);
#1050=DIRECTION('',(0.,0.500000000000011,-0.866025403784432));
#1051=VECTOR('',#1050,1.);
#1052=CARTESIAN_POINT('',(0.6858,2.10879835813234,-2.82370457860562));
#1053=LINE('',#1052,#1051);
#1054=EDGE_CURVE('E623',#1047,#361,#1053,.T.);
#1055=ORIENTED_EDGE('',*,*,#1054,.T.);
#1056=EDGE_LOOP('',(#763,#771,#780,#786,#787,#795,#804,#810,#811,#819,#828,#834,#835,#843,#852,
#858,#859,#867,#876,#882,#883,#891,#900,#906,#907,#915,#924,#930,#931,#939,#948,#954,#955,#963,
#972,#978,#979,#987,#996,#1002,#1003,#1011,#1020,#1028,#1032,#1040,#1049,#1055));
#1057=FACE_BOUND('',#1056,.T.);
#1058=ADVANCED_FACE('F488',(#762,#1057),#759,.T.);
#1059=CARTESIAN_POINT('',(0.6856,3.12817347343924,-2.28458355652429));
#1060=CARTESIAN_POINT('',(0.771328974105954,3.0901468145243,-2.26262885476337));
#1061=CARTESIAN_POINT('',(0.857053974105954,3.05211343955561,-2.240670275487));
#1062=CARTESIAN_POINT('',(1.08579439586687,2.95060617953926,-2.18206503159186));
#1063=CARTESIAN_POINT('',(1.2288027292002,2.88712031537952,-2.1454114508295));
#1064=CARTESIAN_POINT('',(1.3718,2.82361575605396,-2.10874707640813));
#1065=B_SPLINE_CURVE_WITH_KNOTS('',3,(#1059,#1060,#1061,#1062,#1063,#1064),.UNSPECIFIED.,.F.,
.F.,(4,2,4),(0.,0.288959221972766,0.7710670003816),.UNSPECIFIED.);
#1066=EDGE_CURVE('E815',#1030,#634,#1065,.T.);
#1067=ORIENTED_EDGE('',*,*,#1066,.F.);
#1068=ORIENTED_EDGE('',*,*,#1031,.F.);
#1069=CARTESIAN_POINT('',(1.3718,3.2380364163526,-1.39094943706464));
#1070=CARTESIAN_POINT('',(1.2288027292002,3.30154097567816,-1.42761381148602));
#1071=CARTESIAN_POINT('',(1.08579439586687,3.36502683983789,-1.46426739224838));
#1072=CARTESIAN_POINT('',(0.857053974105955,3.46653409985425,-1.52287263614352));
#1073=CARTESIAN_POINT('',(0.771328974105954,3.50456747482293,-1.54483121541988));
#1074=CARTESIAN_POINT('',(0.685600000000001,3.54259413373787,-1.5667859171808));
#1075=B_SPLINE_CURVE_WITH_KNOTS('',3,(#1069,#1070,#1071,#1072,#1073,#1074),.UNSPECIFIED.,.F.,
.F.,(4,2,4),(0.,0.482107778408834,0.7710670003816),.UNSPECIFIED.);
#1076=EDGE_CURVE('E893',#640,#1026,#1075,.T.);
#1077=ORIENTED_EDGE('',*,*,#1076,.F.);
#1078=ORIENTED_EDGE('',*,*,#641,.T.);
#1079=EDGE_LOOP('',(#1067,#1068,#1077,#1078));
#1080=FACE_BOUND('',#1079,.T.);
#1081=ADVANCED_FACE('F822',(#1080),#23,.T.);
#1082=DIRECTION('',(0.,1.,0.));
#1083=VECTOR('',#1082,1.);
#1084=CARTESIAN_POINT('',(1.3716,3.14783743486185,0.414420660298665));
#1085=LINE('',#1084,#1083);
#1086=CARTESIAN_POINT('',(1.3716,3.14783743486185,0.414420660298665));
#1087=VERTEX_POINT('',#1086);
#1088=EDGE_CURVE('E1271',#1087,#398,#1085,.T.);
#1089=ORIENTED_EDGE('',*,*,#1088,.F.);
#1090=CARTESIAN_POINT('',(1.3716,3.14783743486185,-0.414420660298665));
#1091=VERTEX_POINT('',#1090);
#1092=EDGE_CURVE('E1246',#1087,#1091,#447,.T.);
#1093=ORIENTED_EDGE('',*,*,#1092,.T.);
#1094=DIRECTION('',(0.,-1.,0.));
#1095=VECTOR('',#1094,1.);
#1096=CARTESIAN_POINT('',(1.3716,3.14783743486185,-0.414420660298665));
#1097=LINE('',#1096,#1095);
#1098=EDGE_CURVE('E881',#402,#1091,#1097,.T.);
#1099=ORIENTED_EDGE('',*,*,#1098,.F.);
#1100=ORIENTED_EDGE('',*,*,#403,.F.);
#1101=EDGE_LOOP('',(#1089,#1093,#1099,#1100));
#1102=FACE_BOUND('',#1101,.T.);
#1103=ADVANCED_FACE('F935',(#1102),#425,.T.);
#1104=CARTESIAN_POINT('',(0.,0.,0.));
#1105=DIRECTION('',(-1.,0.,0.));
#1106=DIRECTION('',(0.,0.,1.));
#1107=AXIS2_PLACEMENT_3D('',#1104,#1105,#1106);
#1108=CYLINDRICAL_SURFACE('',#1107,3.175);
#1109=CARTESIAN_POINT('',(13.1064,0.,0.));
#1110=DIRECTION('',(-1.,0.,0.));
#1111=DIRECTION('',(0.,0.,1.));
#1112=AXIS2_PLACEMENT_3D('',#1109,#1110,#1111);
#1113=CIRCLE('',#1112,3.175);
#1114=CARTESIAN_POINT('',(13.1064,0.,3.175));
#1115=VERTEX_POINT('',#1114);
#1116=EDGE_CURVE('E1251',#1115,#1115,#1113,.T.);
#1117=ORIENTED_EDGE('',*,*,#1116,.T.);
#1118=EDGE_LOOP('',(#1117));
#1119=FACE_BOUND('',#1118,.T.);
#1120=ORIENTED_EDGE('',*,*,#651,.F.);
#1121=DIRECTION('',(1.,0.,0.));
#1122=VECTOR('',#1121,1.);
#1123=CARTESIAN_POINT('',(0.942975,2.93331751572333,-1.21501989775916));
#1124=LINE('',#1123,#1122);
#1125=CARTESIAN_POINT('',(0.942975,2.93331751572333,-1.21501989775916));
#1126=VERTEX_POINT('',#1125);
#1127=EDGE_CURVE('E886',#1126,#648,#1124,.T.);
#1128=ORIENTED_EDGE('',*,*,#1127,.F.);
#1129=CARTESIAN_POINT('',(0.942975,0.,0.));
#1130=DIRECTION('',(-1.,0.,0.));
#1131=DIRECTION('',(0.,0.,-1.));
#1132=AXIS2_PLACEMENT_3D('',#1129,#1130,#1131);
#1133=CIRCLE('',#1132,3.175);
#1134=CARTESIAN_POINT('',(0.942975,3.14783743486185,-0.414420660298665));
#1135=VERTEX_POINT('',#1134);
#1136=EDGE_CURVE('E877',#1135,#1126,#1133,.T.);
#1137=ORIENTED_EDGE('',*,*,#1136,.F.);
#1138=DIRECTION('',(1.,0.,0.));
#1139=VECTOR('',#1138,1.);
#1140=CARTESIAN_POINT('',(0.942975,3.14783743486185,-0.414420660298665));
#1141=LINE('',#1140,#1139);
#1142=EDGE_CURVE('E890',#1135,#1091,#1141,.T.);
#1143=ORIENTED_EDGE('',*,*,#1142,.T.);
#1144=ORIENTED_EDGE('',*,*,#1092,.F.);
#1145=DIRECTION('',(1.,0.,0.));
#1146=VECTOR('',#1145,1.);
#1147=CARTESIAN_POINT('',(0.942975,3.14783743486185,0.414420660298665));
#1148=LINE('',#1147,#1146);
#1149=CARTESIAN_POINT('',(0.942975,3.14783743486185,0.414420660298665));
#1150=VERTEX_POINT('',#1149);
#1151=EDGE_CURVE('E1277',#1150,#1087,#1148,.T.);
#1152=ORIENTED_EDGE('',*,*,#1151,.F.);
#1153=CARTESIAN_POINT('',(0.942975,0.,0.));
#1154=DIRECTION('',(-1.,0.,0.));
#1155=DIRECTION('',(0.,0.500000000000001,-0.866025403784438));
#1156=AXIS2_PLACEMENT_3D('',#1153,#1154,#1155);
#1157=CIRCLE('',#1156,3.175);
#1158=CARTESIAN_POINT('',(0.942975,2.93331751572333,1.21501989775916));
#1159=VERTEX_POINT('',#1158);
#1160=EDGE_CURVE('E1368',#1159,#1150,#1157,.T.);
#1161=ORIENTED_EDGE('',*,*,#1160,.F.);
#1162=DIRECTION('',(1.,0.,0.));
#1163=VECTOR('',#1162,1.);
#1164=CARTESIAN_POINT('',(0.942975,2.93331751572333,1.21501989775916));
#1165=LINE('',#1164,#1163);
#1166=EDGE_CURVE('E1542',#1159,#665,#1165,.T.);
#1167=ORIENTED_EDGE('',*,*,#1166,.T.);
#1168=ORIENTED_EDGE('',*,*,#666,.F.);
#1169=DIRECTION('',(1.,0.,0.));
#1170=VECTOR('',#1169,1.);
#1171=CARTESIAN_POINT('',(0.942975,2.51889685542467,1.93281753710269));
#1172=LINE('',#1171,#1170);
#1173=CARTESIAN_POINT('',(0.942975,2.51889685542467,1.93281753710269));
#1174=VERTEX_POINT('',#1173);
#1175=EDGE_CURVE('E651',#1174,#661,#1172,.T.);
#1176=ORIENTED_EDGE('',*,*,#1175,.F.);
#1177=CARTESIAN_POINT('',(0.942975,0.,0.));
#1178=DIRECTION('',(-1.,0.,0.));
#1179=DIRECTION('',(0.,0.86602540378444,-0.499999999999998));
#1180=AXIS2_PLACEMENT_3D('',#1177,#1178,#1179);
#1181=CIRCLE('',#1180,3.175);
#1182=CARTESIAN_POINT('',(0.942975,1.93281753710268,2.51889685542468));
#1183=VERTEX_POINT('',#1182);
#1184=EDGE_CURVE('E643',#1183,#1174,#1181,.T.);
#1185=ORIENTED_EDGE('',*,*,#1184,.F.);
#1186=DIRECTION('',(1.,0.,0.));
#1187=VECTOR('',#1186,1.);
#1188=CARTESIAN_POINT('',(0.942975,1.93281753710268,2.51889685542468));
#1189=LINE('',#1188,#1187);
#1190=EDGE_CURVE('E48',#1183,#431,#1189,.T.);
#1191=ORIENTED_EDGE('',*,*,#1190,.T.);
#1192=ORIENTED_EDGE('',*,*,#448,.F.);
#1193=DIRECTION('',(1.,0.,0.));
#1194=VECTOR('',#1193,1.);
#1195=CARTESIAN_POINT('',(0.942975,1.21501989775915,2.93331751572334));
#1196=LINE('',#1195,#1194);
#1197=CARTESIAN_POINT('',(0.942975,1.21501989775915,2.93331751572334));
#1198=VERTEX_POINT('',#1197);
#1199=EDGE_CURVE('E667',#1198,#440,#1196,.T.);
#1200=ORIENTED_EDGE('',*,*,#1199,.F.);
#1201=CARTESIAN_POINT('',(0.942975,0.,0.));
#1202=DIRECTION('',(-1.,0.,0.));
#1203=DIRECTION('',(0.,1.,0.));
#1204=AXIS2_PLACEMENT_3D('',#1201,#1202,#1203);
#1205=CIRCLE('',#1204,3.175);
#1206=CARTESIAN_POINT('',(0.942975,0.414420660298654,3.14783743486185));
#1207=VERTEX_POINT('',#1206);
#1208=EDGE_CURVE('E658',#1207,#1198,#1205,.T.);
#1209=ORIENTED_EDGE('',*,*,#1208,.F.);
#1210=DIRECTION('',(1.,0.,0.));
#1211=VECTOR('',#1210,1.);
#1212=CARTESIAN_POINT('',(0.942975,0.414420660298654,3.14783743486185));
#1213=LINE('',#1212,#1211);
#1214=EDGE_CURVE('E55',#1207,#458,#1213,.T.);
#1215=ORIENTED_EDGE('',*,*,#1214,.T.);
#1216=ORIENTED_EDGE('',*,*,#470,.F.);
#1217=DIRECTION('',(1.,0.,0.));
#1218=VECTOR('',#1217,1.);
#1219=CARTESIAN_POINT('',(0.942975,-0.414420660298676,3.14783743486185));
#1220=LINE('',#1219,#1218);
#1221=CARTESIAN_POINT('',(0.942975,-0.414420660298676,3.14783743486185));
#1222=VERTEX_POINT('',#1221);
#1223=EDGE_CURVE('E683',#1222,#467,#1220,.T.);
#1224=ORIENTED_EDGE('',*,*,#1223,.F.);
#1225=CARTESIAN_POINT('',(0.942975,0.,0.));
#1226=DIRECTION('',(-1.,0.,0.));
#1227=DIRECTION('',(0.,0.866025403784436,0.500000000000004));
#1228=AXIS2_PLACEMENT_3D('',#1225,#1226,#1227);
#1229=CIRCLE('',#1228,3.175);
#1230=CARTESIAN_POINT('',(0.942975,-1.21501989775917,2.93331751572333));
#1231=VERTEX_POINT('',#1230);
#1232=EDGE_CURVE('E674',#1231,#1222,#1229,.T.);
#1233=ORIENTED_EDGE('',*,*,#1232,.F.);
#1234=DIRECTION('',(1.,0.,0.));
#1235=VECTOR('',#1234,1.);
#1236=CARTESIAN_POINT('',(0.942975,-1.21501989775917,2.93331751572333));
#1237=LINE('',#1236,#1235);
#1238=EDGE_CURVE('E670',#1231,#480,#1237,.T.);
#1239=ORIENTED_EDGE('',*,*,#1238,.T.);
#1240=ORIENTED_EDGE('',*,*,#492,.F.);
#1241=DIRECTION('',(1.,0.,0.));
#1242=VECTOR('',#1241,1.);
#1243=CARTESIAN_POINT('',(0.942975,-1.9328175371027,2.51889685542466));
#1244=LINE('',#1243,#1242);
#1245=CARTESIAN_POINT('',(0.942975,-1.9328175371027,2.51889685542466));
#1246=VERTEX_POINT('',#1245);
#1247=EDGE_CURVE('E700',#1246,#489,#1244,.T.);
#1248=ORIENTED_EDGE('',*,*,#1247,.F.);
#1249=CARTESIAN_POINT('',(0.942975,0.,0.));
#1250=DIRECTION('',(-1.,0.,0.));
#1251=DIRECTION('',(0.,0.499999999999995,0.866025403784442));
#1252=AXIS2_PLACEMENT_3D('',#1249,#1250,#1251);
#1253=CIRCLE('',#1252,3.175);
#1254=CARTESIAN_POINT('',(0.942975,-2.51889685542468,1.93281753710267));
#1255=VERTEX_POINT('',#1254);
#1256=EDGE_CURVE('E691',#1255,#1246,#1253,.T.);
#1257=ORIENTED_EDGE('',*,*,#1256,.F.);
#1258=DIRECTION('',(1.,0.,0.));
#1259=VECTOR('',#1258,1.);
#1260=CARTESIAN_POINT('',(0.942975,-2.51889685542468,1.93281753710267));
#1261=LINE('',#1260,#1259);
#1262=EDGE_CURVE('E686',#1255,#502,#1261,.T.);
#1263=ORIENTED_EDGE('',*,*,#1262,.T.);
#1264=ORIENTED_EDGE('',*,*,#514,.F.);
#1265=DIRECTION('',(1.,0.,0.));
#1266=VECTOR('',#1265,1.);
#1267=CARTESIAN_POINT('',(0.942975,-2.93331751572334,1.21501989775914));
#1268=LINE('',#1267,#1266);
#1269=CARTESIAN_POINT('',(0.942975,-2.93331751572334,1.21501989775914));
#1270=VERTEX_POINT('',#1269);
#1271=EDGE_CURVE('E717',#1270,#511,#1268,.T.);
#1272=ORIENTED_EDGE('',*,*,#1271,.F.);
#1273=CARTESIAN_POINT('',(0.942975,0.,0.));
#1274=DIRECTION('',(-1.,0.,0.));
#1275=DIRECTION('',(0.,0.,1.));
#1276=AXIS2_PLACEMENT_3D('',#1273,#1274,#1275);
#1277=CIRCLE('',#1276,3.175);
#1278=CARTESIAN_POINT('',(0.942975,-3.14783743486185,0.414420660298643));
#1279=VERTEX_POINT('',#1278);
#1280=EDGE_CURVE('E708',#1279,#1270,#1277,.T.);
#1281=ORIENTED_EDGE('',*,*,#1280,.F.);
#1282=DIRECTION('',(1.,0.,0.));
#1283=VECTOR('',#1282,1.);
#1284=CARTESIAN_POINT('',(0.942975,-3.14783743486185,0.414420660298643));
#1285=LINE('',#1284,#1283);
#1286=EDGE_CURVE('E703',#1279,#524,#1285,.T.);
#1287=ORIENTED_EDGE('',*,*,#1286,.T.);
#1288=ORIENTED_EDGE('',*,*,#536,.F.);
#1289=DIRECTION('',(1.,0.,0.));
#1290=VECTOR('',#1289,1.);
#1291=CARTESIAN_POINT('',(0.942975,-3.14783743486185,-0.414420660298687));
#1292=LINE('',#1291,#1290);
#1293=CARTESIAN_POINT('',(0.942975,-3.14783743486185,-0.414420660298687));
#1294=VERTEX_POINT('',#1293);
#1295=EDGE_CURVE('E734',#1294,#533,#1292,.T.);
#1296=ORIENTED_EDGE('',*,*,#1295,.F.);
#1297=CARTESIAN_POINT('',(0.942975,0.,0.));
#1298=DIRECTION('',(-1.,0.,0.));
#1299=DIRECTION('',(0.,-0.500000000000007,0.866025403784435));
#1300=AXIS2_PLACEMENT_3D('',#1297,#1298,#1299);
#1301=CIRCLE('',#1300,3.175);
#1302=CARTESIAN_POINT('',(0.942975,-2.93331751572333,-1.21501989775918));
#1303=VERTEX_POINT('',#1302);
#1304=EDGE_CURVE('E725',#1303,#1294,#1301,.T.);
#1305=ORIENTED_EDGE('',*,*,#1304,.F.);
#1306=DIRECTION('',(1.,0.,0.));
#1307=VECTOR('',#1306,1.);
#1308=CARTESIAN_POINT('',(0.942975,-2.93331751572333,-1.21501989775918));
#1309=LINE('',#1308,#1307);
#1310=EDGE_CURVE('E720',#1303,#546,#1309,.T.);
#1311=ORIENTED_EDGE('',*,*,#1310,.T.);
#1312=ORIENTED_EDGE('',*,*,#558,.F.);
#1313=DIRECTION('',(1.,0.,0.));
#1314=VECTOR('',#1313,1.);
#1315=CARTESIAN_POINT('',(0.942975,-2.51889685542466,-1.93281753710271));
#1316=LINE('',#1315,#1314);
#1317=CARTESIAN_POINT('',(0.942975,-2.51889685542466,-1.93281753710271));
#1318=VERTEX_POINT('',#1317);
#1319=EDGE_CURVE('E751',#1318,#555,#1316,.T.);
#1320=ORIENTED_EDGE('',*,*,#1319,.F.);
#1321=CARTESIAN_POINT('',(0.942975,0.,0.));
#1322=DIRECTION('',(-1.,0.,0.));
#1323=DIRECTION('',(0.,-0.866025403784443,0.499999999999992));
#1324=AXIS2_PLACEMENT_3D('',#1321,#1322,#1323);
#1325=CIRCLE('',#1324,3.175);
#1326=CARTESIAN_POINT('',(0.942975,-1.93281753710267,-2.51889685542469));
#1327=VERTEX_POINT('',#1326);
#1328=EDGE_CURVE('E742',#1327,#1318,#1325,.T.);
#1329=ORIENTED_EDGE('',*,*,#1328,.F.);
#1330=DIRECTION('',(1.,0.,0.));
#1331=VECTOR('',#1330,1.);
#1332=CARTESIAN_POINT('',(0.942975,-1.93281753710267,-2.51889685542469));
#1333=LINE('',#1332,#1331);
#1334=EDGE_CURVE('E737',#1327,#568,#1333,.T.);
#1335=ORIENTED_EDGE('',*,*,#1334,.T.);
#1336=ORIENTED_EDGE('',*,*,#580,.F.);
#1337=DIRECTION('',(1.,0.,0.));
#1338=VECTOR('',#1337,1.);
#1339=CARTESIAN_POINT('',(0.942975,-1.21501989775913,-2.93331751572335));
#1340=LINE('',#1339,#1338);
#1341=CARTESIAN_POINT('',(0.942975,-1.21501989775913,-2.93331751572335));
#1342=VERTEX_POINT('',#1341);
#1343=EDGE_CURVE('E768',#1342,#577,#1340,.T.);
#1344=ORIENTED_EDGE('',*,*,#1343,.F.);
#1345=CARTESIAN_POINT('',(0.942975,0.,0.));
#1346=DIRECTION('',(-1.,0.,0.));
#1347=DIRECTION('',(0.,-1.,0.));
#1348=AXIS2_PLACEMENT_3D('',#1345,#1346,#1347);
#1349=CIRCLE('',#1348,3.175);
#1350=CARTESIAN_POINT('',(0.942975,-0.414420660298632,-3.14783743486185));
#1351=VERTEX_POINT('',#1350);
#1352=EDGE_CURVE('E759',#1351,#1342,#1349,.T.);
#1353=ORIENTED_EDGE('',*,*,#1352,.F.);
#1354=DIRECTION('',(1.,0.,0.));
#1355=VECTOR('',#1354,1.);
#1356=CARTESIAN_POINT('',(0.942975,-0.414420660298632,-3.14783743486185));
#1357=LINE('',#1356,#1355);
#1358=EDGE_CURVE('E754',#1351,#590,#1357,.T.);
#1359=ORIENTED_EDGE('',*,*,#1358,.T.);
#1360=ORIENTED_EDGE('',*,*,#602,.F.);
#1361=DIRECTION('',(1.,0.,0.));
#1362=VECTOR('',#1361,1.);
#1363=CARTESIAN_POINT('',(0.942975,0.414420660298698,-3.14783743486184));
#1364=LINE('',#1363,#1362);
#1365=CARTESIAN_POINT('',(0.942975,0.414420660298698,-3.14783743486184));
#1366=VERTEX_POINT('',#1365);
#1367=EDGE_CURVE('E785',#1366,#599,#1364,.T.);
#1368=ORIENTED_EDGE('',*,*,#1367,.F.);
#1369=CARTESIAN_POINT('',(0.942975,0.,0.));
#1370=DIRECTION('',(-1.,0.,0.));
#1371=DIRECTION('',(0.,-0.866025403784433,-0.50000000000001));
#1372=AXIS2_PLACEMENT_3D('',#1369,#1370,#1371);
#1373=CIRCLE('',#1372,3.175);
#1374=CARTESIAN_POINT('',(0.942975,1.21501989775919,-2.93331751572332));
#1375=VERTEX_POINT('',#1374);
#1376=EDGE_CURVE('E776',#1375,#1366,#1373,.T.);
#1377=ORIENTED_EDGE('',*,*,#1376,.F.);
#1378=DIRECTION('',(1.,0.,0.));
#1379=VECTOR('',#1378,1.);
#1380=CARTESIAN_POINT('',(0.942975,1.21501989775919,-2.93331751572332));
#1381=LINE('',#1380,#1379);
#1382=EDGE_CURVE('E771',#1375,#612,#1381,.T.);
#1383=ORIENTED_EDGE('',*,*,#1382,.T.);
#1384=ORIENTED_EDGE('',*,*,#624,.F.);
#1385=DIRECTION('',(1.,0.,0.));
#1386=VECTOR('',#1385,1.);
#1387=CARTESIAN_POINT('',(0.942975,1.93281753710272,-2.51889685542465));
#1388=LINE('',#1387,#1386);
#1389=CARTESIAN_POINT('',(0.942975,1.93281753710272,-2.51889685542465));
#1390=VERTEX_POINT('',#1389);
#1391=EDGE_CURVE('E802',#1390,#621,#1388,.T.);
#1392=ORIENTED_EDGE('',*,*,#1391,.F.);
#1393=CARTESIAN_POINT('',(0.942975,0.,0.));
#1394=DIRECTION('',(-1.,0.,0.));
#1395=DIRECTION('',(0.,-0.499999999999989,-0.866025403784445));
#1396=AXIS2_PLACEMENT_3D('',#1393,#1394,#1395);
#1397=CIRCLE('',#1396,3.175);
#1398=CARTESIAN_POINT('',(0.942975,2.5188968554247,-1.93281753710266));
#1399=VERTEX_POINT('',#1398);
#1400=EDGE_CURVE('E793',#1399,#1390,#1397,.T.);
#1401=ORIENTED_EDGE('',*,*,#1400,.F.);
#1402=DIRECTION('',(1.,0.,0.));
#1403=VECTOR('',#1402,1.);
#1404=CARTESIAN_POINT('',(0.942975,2.5188968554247,-1.93281753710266));
#1405=LINE('',#1404,#1403);
#1406=EDGE_CURVE('E788',#1399,#636,#1405,.T.);
#1407=ORIENTED_EDGE('',*,*,#1406,.T.);
#1408=EDGE_LOOP('',(#1120,#1128,#1137,#1143,#1144,#1152,#1161,#1167,#1168,#1176,#1185,#1191,
#1192,#1200,#1209,#1215,#1216,#1224,#1233,#1239,#1240,#1248,#1257,#1263,#1264,#1272,#1281,#1287,
#1288,#1296,#1305,#1311,#1312,#1320,#1329,#1335,#1336,#1344,#1353,#1359,#1360,#1368,#1377,#1383,
#1384,#1392,#1401,#1407));
#1409=FACE_BOUND('',#1408,.T.);
#1410=ADVANCED_FACE('F932',(#1119,#1409),#1108,.T.);
#1411=CARTESIAN_POINT('',(16.66875,0.,0.));
#1412=DIRECTION('',(-1.,0.,0.));
#1413=DIRECTION('',(0.,0.,1.));
#1414=AXIS2_PLACEMENT_3D('',#1411,#1412,#1413);
#1415=CONICAL_SURFACE('',#1414,2.41935,0.209022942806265);
#1416=ORIENTED_EDGE('',*,*,#1116,.F.);
#1417=EDGE_LOOP('',(#1416));
#1418=FACE_BOUND('',#1417,.T.);
#1419=CARTESIAN_POINT('',(16.66875,0.,0.));
#1420=DIRECTION('',(-1.,0.,0.));
#1421=DIRECTION('',(0.,0.,1.));
#1422=AXIS2_PLACEMENT_3D('',#1419,#1420,#1421);
#1423=CIRCLE('',#1422,2.41935);
#1424=CARTESIAN_POINT('',(16.66875,0.,2.41935));
#1425=VERTEX_POINT('',#1424);
#1426=EDGE_CURVE('E1255',#1425,#1425,#1423,.T.);
#1427=ORIENTED_EDGE('',*,*,#1426,.T.);
#1428=EDGE_LOOP('',(#1427));
#1429=FACE_BOUND('',#1428,.T.);
#1430=ADVANCED_FACE('F928',(#1418,#1429),#1415,.T.);
#1431=CARTESIAN_POINT('',(16.66875,0.,0.));
#1432=DIRECTION('',(-1.,0.,0.));
#1433=DIRECTION('',(0.,0.,1.));
#1434=AXIS2_PLACEMENT_3D('',#1431,#1432,#1433);
#1435=CONICAL_SURFACE('',#1434,2.41935,0.785398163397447);
#1436=CARTESIAN_POINT('',(16.891,0.,0.));
#1437=DIRECTION('',(-1.,0.,0.));
#1438=DIRECTION('',(0.,0.,1.));
#1439=AXIS2_PLACEMENT_3D('',#1436,#1437,#1438);
#1440=CIRCLE('',#1439,2.1971);
#1441=CARTESIAN_POINT('',(16.891,0.,2.1971));
#1442=VERTEX_POINT('',#1441);
#1443=EDGE_CURVE('E1258',#1442,#1442,#1440,.T.);
#1444=ORIENTED_EDGE('',*,*,#1443,.T.);
#1445=EDGE_LOOP('',(#1444));
#1446=FACE_BOUND('',#1445,.T.);
#1447=ORIENTED_EDGE('',*,*,#1426,.F.);
#1448=EDGE_LOOP('',(#1447));
#1449=FACE_BOUND('',#1448,.T.);
#1450=ADVANCED_FACE('F924',(#1446,#1449),#1435,.T.);
#1451=CARTESIAN_POINT('',(0.,0.,0.));
#1452=DIRECTION('',(-1.,0.,0.));
#1453=DIRECTION('',(0.,0.,1.));
#1454=AXIS2_PLACEMENT_3D('',#1451,#1452,#1453);
#1455=CYLINDRICAL_SURFACE('',#1454,2.1971);
#1456=CARTESIAN_POINT('',(19.05,0.,0.));
#1457=DIRECTION('',(-1.,0.,0.));
#1458=DIRECTION('',(0.,0.,1.));
#1459=AXIS2_PLACEMENT_3D('',#1456,#1457,#1458);
#1460=CIRCLE('',#1459,2.1971);
#1461=CARTESIAN_POINT('',(19.05,0.,2.1971));
#1462=VERTEX_POINT('',#1461);
#1463=EDGE_CURVE('E1262',#1462,#1462,#1460,.T.);
#1464=ORIENTED_EDGE('',*,*,#1463,.T.);
#1465=EDGE_LOOP('',(#1464));
#1466=FACE_BOUND('',#1465,.T.);
#1467=ORIENTED_EDGE('',*,*,#1443,.F.);
#1468=EDGE_LOOP('',(#1467));
#1469=FACE_BOUND('',#1468,.T.);
#1470=ADVANCED_FACE('F920',(#1466,#1469),#1455,.T.);
#1471=CARTESIAN_POINT('',(19.05,2.1971,0.));
#1472=DIRECTION('',(1.,0.,0.));
#1473=DIRECTION('',(0.,0.,-1.));
#1474=AXIS2_PLACEMENT_3D('',#1471,#1472,#1473);
#1475=PLANE('',#1474);
#1476=ORIENTED_EDGE('',*,*,#1463,.F.);
#1477=EDGE_LOOP('',(#1476));
#1478=FACE_BOUND('',#1477,.T.);
#1479=ADVANCED_FACE('F917',(#1478),#1475,.T.);
#1480=CARTESIAN_POINT('',(0.942975,3.14783743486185,-0.414420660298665));
#1481=DIRECTION('',(0.,0.,1.));
#1482=DIRECTION('',(1.,0.,0.));
#1483=AXIS2_PLACEMENT_3D('',#1480,#1481,#1482);
#1484=PLANE('',#1483);
#1485=DIRECTION('',(0.,-1.,0.));
#1486=VECTOR('',#1485,1.);
#1487=CARTESIAN_POINT('',(0.942975,3.14783743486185,-0.414420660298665));
#1488=LINE('',#1487,#1486);
#1489=CARTESIAN_POINT('',(0.942975,3.49979907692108,-0.414420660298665));
#1490=VERTEX_POINT('',#1489);
#1491=EDGE_CURVE('E884',#1490,#1135,#1488,.T.);
#1492=ORIENTED_EDGE('',*,*,#1491,.F.);
#1493=DIRECTION('',(1.,0.,0.));
#1494=VECTOR('',#1493,1.);
#1495=CARTESIAN_POINT('',(0.6858,3.49979907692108,-0.414420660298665));
#1496=LINE('',#1495,#1494);
#1497=EDGE_CURVE('E871',#1009,#1490,#1496,.T.);
#1498=ORIENTED_EDGE('',*,*,#1497,.F.);
#1499=ORIENTED_EDGE('',*,*,#1010,.F.);
#1500=ORIENTED_EDGE('',*,*,#416,.T.);
#1501=ORIENTED_EDGE('',*,*,#1098,.T.);
#1502=ORIENTED_EDGE('',*,*,#1142,.F.);
#1503=EDGE_LOOP('',(#1492,#1498,#1499,#1500,#1501,#1502));
#1504=FACE_BOUND('',#1503,.T.);
#1505=ADVANCED_FACE('F913',(#1504),#1484,.F.);
#1506=CARTESIAN_POINT('',(0.942975,2.93331751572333,-1.21501989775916));
#1507=DIRECTION('',(0.,-0.500000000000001,-0.866025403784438));
#1508=DIRECTION('',(0.,0.866025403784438,-0.500000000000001));
#1509=AXIS2_PLACEMENT_3D('',#1506,#1507,#1508);
#1510=PLANE('',#1509);
#1511=ORIENTED_EDGE('',*,*,#649,.T.);
#1512=ORIENTED_EDGE('',*,*,#1076,.T.);
#1513=ORIENTED_EDGE('',*,*,#1027,.F.);
#1514=DIRECTION('',(1.,0.,0.));
#1515=VECTOR('',#1514,1.);
#1516=CARTESIAN_POINT('',(0.6858,3.23812523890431,-1.39100071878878));
#1517=LINE('',#1516,#1515);
#1518=CARTESIAN_POINT('',(0.942975,3.23812523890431,-1.39100071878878));
#1519=VERTEX_POINT('',#1518);
#1520=EDGE_CURVE('E872',#1018,#1519,#1517,.T.);
#1521=ORIENTED_EDGE('',*,*,#1520,.T.);
#1522=DIRECTION('',(0.,0.866025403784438,-0.500000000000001));
#1523=VECTOR('',#1522,1.);
#1524=CARTESIAN_POINT('',(0.942975,2.93331751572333,-1.21501989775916));
#1525=LINE('',#1524,#1523);
#1526=EDGE_CURVE('E880',#1126,#1519,#1525,.T.);
#1527=ORIENTED_EDGE('',*,*,#1526,.F.);
#1528=ORIENTED_EDGE('',*,*,#1127,.T.);
#1529=EDGE_LOOP('',(#1511,#1512,#1513,#1521,#1527,#1528));
#1530=FACE_BOUND('',#1529,.T.);
#1531=ADVANCED_FACE('F908',(#1530),#1510,.F.);
#1532=CARTESIAN_POINT('',(0.942975,0.,0.));
#1533=DIRECTION('',(1.,0.,0.));
#1534=DIRECTION('',(0.,0.,-1.));
#1535=AXIS2_PLACEMENT_3D('',#1532,#1533,#1534);
#1536=PLANE('',#1535);
#1537=CARTESIAN_POINT('',(0.942975,0.,0.));
#1538=DIRECTION('',(1.,0.,0.));
#1539=DIRECTION('',(0.,0.,-1.));
#1540=AXIS2_PLACEMENT_3D('',#1537,#1538,#1539);
#1541=CIRCLE('',#1540,3.52425);
#1542=EDGE_CURVE('E1283',#1490,#1519,#1541,.F.);
#1543=ORIENTED_EDGE('',*,*,#1542,.F.);
#1544=ORIENTED_EDGE('',*,*,#1491,.T.);
#1545=ORIENTED_EDGE('',*,*,#1136,.T.);
#1546=ORIENTED_EDGE('',*,*,#1526,.T.);
#1547=EDGE_LOOP('',(#1543,#1544,#1545,#1546));
#1548=FACE_BOUND('',#1547,.T.);
#1549=ADVANCED_FACE('F912',(#1548),#1536,.T.);
#1550=CARTESIAN_POINT('',(0.6858,0.,0.));
#1551=DIRECTION('',(1.,0.,0.));
#1552=DIRECTION('',(0.,0.,-1.));
#1553=AXIS2_PLACEMENT_3D('',#1550,#1551,#1552);
#1554=CYLINDRICAL_SURFACE('',#1553,3.52425);
#1555=ORIENTED_EDGE('',*,*,#1542,.T.);
#1556=ORIENTED_EDGE('',*,*,#1520,.F.);
#1557=ORIENTED_EDGE('',*,*,#1019,.F.);
#1558=ORIENTED_EDGE('',*,*,#1497,.T.);
#1559=EDGE_LOOP('',(#1555,#1556,#1557,#1558));
#1560=FACE_BOUND('',#1559,.T.);
#1561=ADVANCED_FACE('F844',(#1560),#1554,.T.);
#1562=CARTESIAN_POINT('',(0.942975,2.93331751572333,1.21501989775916));
#1563=DIRECTION('',(0.,-0.500000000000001,0.866025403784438));
#1564=DIRECTION('',(0.,-0.866025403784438,-0.500000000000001));
#1565=AXIS2_PLACEMENT_3D('',#1562,#1563,#1564);
#1566=PLANE('',#1565);
#1567=DIRECTION('',(0.,-0.866025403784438,-0.500000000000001));
#1568=VECTOR('',#1567,1.);
#1569=CARTESIAN_POINT('',(0.942975,2.93331751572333,1.21501989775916));
#1570=LINE('',#1569,#1568);
#1571=CARTESIAN_POINT('',(0.942975,3.23812523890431,1.39100071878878));
#1572=VERTEX_POINT('',#1571);
#1573=EDGE_CURVE('E1537',#1572,#1159,#1570,.T.);
#1574=ORIENTED_EDGE('',*,*,#1573,.F.);
#1575=DIRECTION('',(1.,0.,0.));
#1576=VECTOR('',#1575,1.);
#1577=CARTESIAN_POINT('',(0.6858,3.23812523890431,1.39100071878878));
#1578=LINE('',#1577,#1576);
#1579=EDGE_CURVE('E637',#985,#1572,#1578,.T.);
#1580=ORIENTED_EDGE('',*,*,#1579,.F.);
#1581=ORIENTED_EDGE('',*,*,#986,.F.);
#1582=ORIENTED_EDGE('',*,*,#62,.T.);
#1583=ORIENTED_EDGE('',*,*,#672,.T.);
#1584=ORIENTED_EDGE('',*,*,#1166,.F.);
#1585=EDGE_LOOP('',(#1574,#1580,#1581,#1582,#1583,#1584));
#1586=FACE_BOUND('',#1585,.T.);
#1587=ADVANCED_FACE('F840',(#1586),#1566,.F.);
#1588=CARTESIAN_POINT('',(0.942975,3.14783743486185,0.414420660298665));
#1589=DIRECTION('',(0.,0.,-1.));
#1590=DIRECTION('',(0.,1.,0.));
#1591=AXIS2_PLACEMENT_3D('',#1588,#1589,#1590);
#1592=PLANE('',#1591);
#1593=ORIENTED_EDGE('',*,*,#1088,.T.);
#1594=ORIENTED_EDGE('',*,*,#399,.T.);
#1595=ORIENTED_EDGE('',*,*,#1001,.F.);
#1596=DIRECTION('',(1.,0.,0.));
#1597=VECTOR('',#1596,1.);
#1598=CARTESIAN_POINT('',(0.6858,3.49979907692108,0.414420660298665));
#1599=LINE('',#1598,#1597);
#1600=CARTESIAN_POINT('',(0.942975,3.49979907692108,0.414420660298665));
#1601=VERTEX_POINT('',#1600);
#1602=EDGE_CURVE('E638',#994,#1601,#1599,.T.);
#1603=ORIENTED_EDGE('',*,*,#1602,.T.);
#1604=DIRECTION('',(0.,1.,0.));
#1605=VECTOR('',#1604,1.);
#1606=CARTESIAN_POINT('',(0.942975,3.14783743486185,0.414420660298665));
#1607=LINE('',#1606,#1605);
#1608=EDGE_CURVE('E1535',#1150,#1601,#1607,.T.);
#1609=ORIENTED_EDGE('',*,*,#1608,.F.);
#1610=ORIENTED_EDGE('',*,*,#1151,.T.);
#1611=EDGE_LOOP('',(#1593,#1594,#1595,#1603,#1609,#1610));
#1612=FACE_BOUND('',#1611,.T.);
#1613=ADVANCED_FACE('F838',(#1612),#1592,.F.);
#1614=CARTESIAN_POINT('',(0.942975,0.,0.));
#1615=DIRECTION('',(1.,0.,0.));
#1616=DIRECTION('',(0.,0.500000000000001,-0.866025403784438));
#1617=AXIS2_PLACEMENT_3D('',#1614,#1615,#1616);
#1618=PLANE('',#1617);
#1619=CARTESIAN_POINT('',(0.942975,0.,0.));
#1620=DIRECTION('',(1.,0.,0.));
#1621=DIRECTION('',(0.,0.,-1.));
#1622=AXIS2_PLACEMENT_3D('',#1619,#1620,#1621);
#1623=CIRCLE('',#1622,3.52425);
#1624=EDGE_CURVE('E1286',#1572,#1601,#1623,.F.);
#1625=ORIENTED_EDGE('',*,*,#1624,.F.);
#1626=ORIENTED_EDGE('',*,*,#1573,.T.);
#1627=ORIENTED_EDGE('',*,*,#1160,.T.);
#1628=ORIENTED_EDGE('',*,*,#1608,.T.);
#1629=EDGE_LOOP('',(#1625,#1626,#1627,#1628));
#1630=FACE_BOUND('',#1629,.T.);
#1631=ADVANCED_FACE('F835',(#1630),#1618,.T.);
#1632=CARTESIAN_POINT('',(0.942975,2.5188968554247,-1.93281753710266));
#1633=DIRECTION('',(0.,0.499999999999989,0.866025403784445));
#1634=DIRECTION('',(0.,-0.866025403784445,0.499999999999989));
#1635=AXIS2_PLACEMENT_3D('',#1632,#1633,#1634);
#1636=PLANE('',#1635);
#1637=DIRECTION('',(0.,-0.866025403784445,0.499999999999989));
#1638=VECTOR('',#1637,1.);
#1639=CARTESIAN_POINT('',(0.942975,2.5188968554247,-1.93281753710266));
#1640=LINE('',#1639,#1638);
#1641=CARTESIAN_POINT('',(0.942975,2.82370457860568,-2.10879835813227));
#1642=VERTEX_POINT('',#1641);
#1643=EDGE_CURVE('E800',#1642,#1399,#1640,.T.);
#1644=ORIENTED_EDGE('',*,*,#1643,.F.);
#1645=DIRECTION('',(1.,0.,0.));
#1646=VECTOR('',#1645,1.);
#1647=CARTESIAN_POINT('',(0.6858,2.82370457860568,-2.10879835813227));
#1648=LINE('',#1647,#1646);
#1649=EDGE_CURVE('E626',#1038,#1642,#1648,.T.);
#1650=ORIENTED_EDGE('',*,*,#1649,.F.);
#1651=ORIENTED_EDGE('',*,*,#1039,.F.);
#1652=ORIENTED_EDGE('',*,*,#1066,.T.);
#1653=ORIENTED_EDGE('',*,*,#637,.T.);
#1654=ORIENTED_EDGE('',*,*,#1406,.F.);
#1655=EDGE_LOOP('',(#1644,#1650,#1651,#1652,#1653,#1654));
#1656=FACE_BOUND('',#1655,.T.);
#1657=ADVANCED_FACE('F831',(#1656),#1636,.F.);
#1658=CARTESIAN_POINT('',(0.942975,1.93281753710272,-2.51889685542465));
#1659=DIRECTION('',(0.,-0.866025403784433,-0.50000000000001));
#1660=DIRECTION('',(0.,0.50000000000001,-0.866025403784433));
#1661=AXIS2_PLACEMENT_3D('',#1658,#1659,#1660);
#1662=PLANE('',#1661);
#1663=ORIENTED_EDGE('',*,*,#622,.T.);
#1664=ORIENTED_EDGE('',*,*,#373,.T.);
#1665=ORIENTED_EDGE('',*,*,#1054,.F.);
#1666=DIRECTION('',(1.,0.,0.));
#1667=VECTOR('',#1666,1.);
#1668=CARTESIAN_POINT('',(0.6858,2.10879835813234,-2.82370457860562));
#1669=LINE('',#1668,#1667);
#1670=CARTESIAN_POINT('',(0.942975,2.10879835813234,-2.82370457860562));
#1671=VERTEX_POINT('',#1670);
#1672=EDGE_CURVE('E608',#1047,#1671,#1669,.T.);
#1673=ORIENTED_EDGE('',*,*,#1672,.T.);
#1674=DIRECTION('',(0.,0.50000000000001,-0.866025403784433));
#1675=VECTOR('',#1674,1.);
#1676=CARTESIAN_POINT('',(0.942975,1.93281753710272,-2.51889685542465));
#1677=LINE('',#1676,#1675);
#1678=EDGE_CURVE('E796',#1390,#1671,#1677,.T.);
#1679=ORIENTED_EDGE('',*,*,#1678,.F.);
#1680=ORIENTED_EDGE('',*,*,#1391,.T.);
#1681=EDGE_LOOP('',(#1663,#1664,#1665,#1673,#1679,#1680));
#1682=FACE_BOUND('',#1681,.T.);
#1683=ADVANCED_FACE('F826',(#1682),#1662,.F.);
#1684=CARTESIAN_POINT('',(0.942975,0.,0.));
#1685=DIRECTION('',(1.,0.,0.));
#1686=DIRECTION('',(0.,-0.499999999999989,-0.866025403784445));
#1687=AXIS2_PLACEMENT_3D('',#1684,#1685,#1686);
#1688=PLANE('',#1687);
#1689=CARTESIAN_POINT('',(0.942975,0.,0.));
#1690=DIRECTION('',(1.,0.,0.));
#1691=DIRECTION('',(0.,0.,-1.));
#1692=AXIS2_PLACEMENT_3D('',#1689,#1690,#1691);
#1693=CIRCLE('',#1692,3.52425);
#1694=EDGE_CURVE('E11',#1642,#1671,#1693,.F.);
#1695=ORIENTED_EDGE('',*,*,#1694,.F.);
#1696=ORIENTED_EDGE('',*,*,#1643,.T.);
#1697=ORIENTED_EDGE('',*,*,#1400,.T.);
#1698=ORIENTED_EDGE('',*,*,#1678,.T.);
#1699=EDGE_LOOP('',(#1695,#1696,#1697,#1698));
#1700=FACE_BOUND('',#1699,.T.);
#1701=ADVANCED_FACE('F830',(#1700),#1688,.T.);
#1702=CARTESIAN_POINT('',(0.942975,1.21501989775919,-2.93331751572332));
#1703=DIRECTION('',(0.,0.866025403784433,0.50000000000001));
#1704=DIRECTION('',(0.,-0.50000000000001,0.866025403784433));
#1705=AXIS2_PLACEMENT_3D('',#1702,#1703,#1704);
#1706=PLANE('',#1705);
#1707=DIRECTION('',(0.,-0.50000000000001,0.866025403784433));
#1708=VECTOR('',#1707,1.);
#1709=CARTESIAN_POINT('',(0.942975,1.21501989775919,-2.93331751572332));
#1710=LINE('',#1709,#1708);
#1711=CARTESIAN_POINT('',(0.942975,1.39100071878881,-3.2381252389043));
#1712=VERTEX_POINT('',#1711);
#1713=EDGE_CURVE('E783',#1712,#1375,#1710,.T.);
#1714=ORIENTED_EDGE('',*,*,#1713,.F.);
#1715=DIRECTION('',(1.,0.,0.));
#1716=VECTOR('',#1715,1.);
#1717=CARTESIAN_POINT('',(0.6858,1.39100071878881,-3.2381252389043));
#1718=LINE('',#1717,#1716);
#1719=EDGE_CURVE('E614',#769,#1712,#1718,.T.);
#1720=ORIENTED_EDGE('',*,*,#1719,.F.);
#1721=ORIENTED_EDGE('',*,*,#770,.F.);
#1722=ORIENTED_EDGE('',*,*,#358,.T.);
#1723=ORIENTED_EDGE('',*,*,#613,.T.);
#1724=ORIENTED_EDGE('',*,*,#1382,.F.);
#1725=EDGE_LOOP('',(#1714,#1720,#1721,#1722,#1723,#1724));
#1726=FACE_BOUND('',#1725,.T.);
#1727=ADVANCED_FACE('F1199',(#1726),#1706,.F.);
#1728=CARTESIAN_POINT('',(0.942975,0.414420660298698,-3.14783743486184));
#1729=DIRECTION('',(0.,-1.,0.));
#1730=DIRECTION('',(0.,0.,-1.));
#1731=AXIS2_PLACEMENT_3D('',#1728,#1729,#1730);
#1732=PLANE('',#1731);
#1733=ORIENTED_EDGE('',*,*,#600,.T.);
#1734=ORIENTED_EDGE('',*,*,#340,.T.);
#1735=ORIENTED_EDGE('',*,*,#785,.F.);
#1736=DIRECTION('',(1.,0.,0.));
#1737=VECTOR('',#1736,1.);
#1738=CARTESIAN_POINT('',(0.6858,0.414420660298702,-3.49979907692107));
#1739=LINE('',#1738,#1737);
#1740=CARTESIAN_POINT('',(0.942975,0.414420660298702,-3.49979907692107));
#1741=VERTEX_POINT('',#1740);
#1742=EDGE_CURVE('E595',#778,#1741,#1739,.T.);
#1743=ORIENTED_EDGE('',*,*,#1742,.T.);
#1744=DIRECTION('',(0.,0.,-1.));
#1745=VECTOR('',#1744,1.);
#1746=CARTESIAN_POINT('',(0.942975,0.414420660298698,-3.14783743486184));
#1747=LINE('',#1746,#1745);
#1748=EDGE_CURVE('E779',#1366,#1741,#1747,.T.);
#1749=ORIENTED_EDGE('',*,*,#1748,.F.);
#1750=ORIENTED_EDGE('',*,*,#1367,.T.);
#1751=EDGE_LOOP('',(#1733,#1734,#1735,#1743,#1749,#1750));
#1752=FACE_BOUND('',#1751,.T.);
#1753=ADVANCED_FACE('F1197',(#1752),#1732,.F.);
#1754=CARTESIAN_POINT('',(0.942975,0.,0.));
#1755=DIRECTION('',(1.,0.,0.));
#1756=DIRECTION('',(0.,-0.866025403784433,-0.50000000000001));
#1757=AXIS2_PLACEMENT_3D('',#1754,#1755,#1756);
#1758=PLANE('',#1757);
#1759=CARTESIAN_POINT('',(0.942975,0.,0.));
#1760=DIRECTION('',(1.,0.,0.));
#1761=DIRECTION('',(0.,0.,-1.));
#1762=AXIS2_PLACEMENT_3D('',#1759,#1760,#1761);
#1763=CIRCLE('',#1762,3.52425);
#1764=EDGE_CURVE('E41',#1712,#1741,#1763,.F.);
#1765=ORIENTED_EDGE('',*,*,#1764,.F.);
#1766=ORIENTED_EDGE('',*,*,#1713,.T.);
#1767=ORIENTED_EDGE('',*,*,#1376,.T.);
#1768=ORIENTED_EDGE('',*,*,#1748,.T.);
#1769=EDGE_LOOP('',(#1765,#1766,#1767,#1768));
#1770=FACE_BOUND('',#1769,.T.);
#1771=ADVANCED_FACE('F1189',(#1770),#1758,.T.);
#1772=CARTESIAN_POINT('',(0.942975,-0.414420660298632,-3.14783743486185));
#1773=DIRECTION('',(0.,1.,0.));
#1774=DIRECTION('',(0.,0.,1.));
#1775=AXIS2_PLACEMENT_3D('',#1772,#1773,#1774);
#1776=PLANE('',#1775);
#1777=DIRECTION('',(0.,0.,1.));
#1778=VECTOR('',#1777,1.);
#1779=CARTESIAN_POINT('',(0.942975,-0.414420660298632,-3.14783743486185));
#1780=LINE('',#1779,#1778);
#1781=CARTESIAN_POINT('',(0.942975,-0.414420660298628,-3.49979907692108));
#1782=VERTEX_POINT('',#1781);
#1783=EDGE_CURVE('E766',#1782,#1351,#1780,.T.);
#1784=ORIENTED_EDGE('',*,*,#1783,.F.);
#1785=DIRECTION('',(1.,0.,0.));
#1786=VECTOR('',#1785,1.);
#1787=CARTESIAN_POINT('',(0.6858,-0.414420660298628,-3.49979907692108));
#1788=LINE('',#1787,#1786);
#1789=EDGE_CURVE('E601',#793,#1782,#1788,.T.);
#1790=ORIENTED_EDGE('',*,*,#1789,.F.);
#1791=ORIENTED_EDGE('',*,*,#794,.F.);
#1792=ORIENTED_EDGE('',*,*,#323,.T.);
#1793=ORIENTED_EDGE('',*,*,#591,.T.);
#1794=ORIENTED_EDGE('',*,*,#1358,.F.);
#1795=EDGE_LOOP('',(#1784,#1790,#1791,#1792,#1793,#1794));
#1796=FACE_BOUND('',#1795,.T.);
#1797=ADVANCED_FACE('F1185',(#1796),#1776,.F.);
#1798=CARTESIAN_POINT('',(0.942975,-1.21501989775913,-2.93331751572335));
#1799=DIRECTION('',(0.,-0.866025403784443,0.499999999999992));
#1800=DIRECTION('',(0.,-0.499999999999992,-0.866025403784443));
#1801=AXIS2_PLACEMENT_3D('',#1798,#1799,#1800);
#1802=PLANE('',#1801);
#1803=ORIENTED_EDGE('',*,*,#578,.T.);
#1804=ORIENTED_EDGE('',*,*,#303,.T.);
#1805=ORIENTED_EDGE('',*,*,#809,.F.);
#1806=DIRECTION('',(1.,0.,0.));
#1807=VECTOR('',#1806,1.);
#1808=CARTESIAN_POINT('',(0.6858,-1.39100071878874,-3.23812523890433));
#1809=LINE('',#1808,#1807);
#1810=CARTESIAN_POINT('',(0.942975,-1.39100071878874,-3.23812523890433));
#1811=VERTEX_POINT('',#1810);
#1812=EDGE_CURVE('E582',#802,#1811,#1809,.T.);
#1813=ORIENTED_EDGE('',*,*,#1812,.T.);
#1814=DIRECTION('',(0.,-0.499999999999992,-0.866025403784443));
#1815=VECTOR('',#1814,1.);
#1816=CARTESIAN_POINT('',(0.942975,-1.21501989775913,-2.93331751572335));
#1817=LINE('',#1816,#1815);
#1818=EDGE_CURVE('E762',#1342,#1811,#1817,.T.);
#1819=ORIENTED_EDGE('',*,*,#1818,.F.);
#1820=ORIENTED_EDGE('',*,*,#1343,.T.);
#1821=EDGE_LOOP('',(#1803,#1804,#1805,#1813,#1819,#1820));
#1822=FACE_BOUND('',#1821,.T.);
#1823=ADVANCED_FACE('F1188',(#1822),#1802,.F.);
#1824=CARTESIAN_POINT('',(0.942975,0.,0.));
#1825=DIRECTION('',(1.,0.,0.));
#1826=DIRECTION('',(0.,-1.,0.));
#1827=AXIS2_PLACEMENT_3D('',#1824,#1825,#1826);
#1828=PLANE('',#1827);
#1829=CARTESIAN_POINT('',(0.942975,0.,0.));
#1830=DIRECTION('',(1.,0.,0.));
#1831=DIRECTION('',(0.,0.,-1.));
#1832=AXIS2_PLACEMENT_3D('',#1829,#1830,#1831);
#1833=CIRCLE('',#1832,3.52425);
#1834=EDGE_CURVE('E1309',#1782,#1811,#1833,.F.);
#1835=ORIENTED_EDGE('',*,*,#1834,.F.);
#1836=ORIENTED_EDGE('',*,*,#1783,.T.);
#1837=ORIENTED_EDGE('',*,*,#1352,.T.);
#1838=ORIENTED_EDGE('',*,*,#1818,.T.);
#1839=EDGE_LOOP('',(#1835,#1836,#1837,#1838));
#1840=FACE_BOUND('',#1839,.T.);
#1841=ADVANCED_FACE('F1155',(#1840),#1828,.T.);
#1842=CARTESIAN_POINT('',(0.942975,-1.93281753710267,-2.51889685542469));
#1843=DIRECTION('',(0.,0.866025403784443,-0.499999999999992));
#1844=DIRECTION('',(0.,0.499999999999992,0.866025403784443));
#1845=AXIS2_PLACEMENT_3D('',#1842,#1843,#1844);
#1846=PLANE('',#1845);
#1847=DIRECTION('',(0.,0.499999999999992,0.866025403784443));
#1848=VECTOR('',#1847,1.);
#1849=CARTESIAN_POINT('',(0.942975,-1.93281753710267,-2.51889685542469));
#1850=LINE('',#1849,#1848);
#1851=CARTESIAN_POINT('',(0.942975,-2.10879835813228,-2.82370457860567));
#1852=VERTEX_POINT('',#1851);
#1853=EDGE_CURVE('E749',#1852,#1327,#1850,.T.);
#1854=ORIENTED_EDGE('',*,*,#1853,.F.);
#1855=DIRECTION('',(1.,0.,0.));
#1856=VECTOR('',#1855,1.);
#1857=CARTESIAN_POINT('',(0.6858,-2.10879835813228,-2.82370457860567));
#1858=LINE('',#1857,#1856);
#1859=EDGE_CURVE('E588',#817,#1852,#1858,.T.);
#1860=ORIENTED_EDGE('',*,*,#1859,.F.);
#1861=ORIENTED_EDGE('',*,*,#818,.F.);
#1862=ORIENTED_EDGE('',*,*,#288,.T.);
#1863=ORIENTED_EDGE('',*,*,#569,.T.);
#1864=ORIENTED_EDGE('',*,*,#1334,.F.);
#1865=EDGE_LOOP('',(#1854,#1860,#1861,#1862,#1863,#1864));
#1866=FACE_BOUND('',#1865,.T.);
#1867=ADVANCED_FACE('F1151',(#1866),#1846,.F.);
#1868=CARTESIAN_POINT('',(0.942975,-2.51889685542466,-1.93281753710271));
#1869=DIRECTION('',(0.,-0.500000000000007,0.866025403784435));
#1870=DIRECTION('',(0.,-0.866025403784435,-0.500000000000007));
#1871=AXIS2_PLACEMENT_3D('',#1868,#1869,#1870);
#1872=PLANE('',#1871);
#1873=ORIENTED_EDGE('',*,*,#556,.T.);
#1874=ORIENTED_EDGE('',*,*,#270,.T.);
#1875=ORIENTED_EDGE('',*,*,#833,.F.);
#1876=DIRECTION('',(1.,0.,0.));
#1877=VECTOR('',#1876,1.);
#1878=CARTESIAN_POINT('',(0.6858,-2.82370457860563,-2.10879835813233));
#1879=LINE('',#1878,#1877);
#1880=CARTESIAN_POINT('',(0.942975,-2.82370457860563,-2.10879835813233));
#1881=VERTEX_POINT('',#1880);
#1882=EDGE_CURVE('E569',#826,#1881,#1879,.T.);
#1883=ORIENTED_EDGE('',*,*,#1882,.T.);
#1884=DIRECTION('',(0.,-0.866025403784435,-0.500000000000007));
#1885=VECTOR('',#1884,1.);
#1886=CARTESIAN_POINT('',(0.942975,-2.51889685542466,-1.93281753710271));
#1887=LINE('',#1886,#1885);
#1888=EDGE_CURVE('E745',#1318,#1881,#1887,.T.);
#1889=ORIENTED_EDGE('',*,*,#1888,.F.);
#1890=ORIENTED_EDGE('',*,*,#1319,.T.);
#1891=EDGE_LOOP('',(#1873,#1874,#1875,#1883,#1889,#1890));
#1892=FACE_BOUND('',#1891,.T.);
#1893=ADVANCED_FACE('F1149',(#1892),#1872,.F.);
#1894=CARTESIAN_POINT('',(0.942975,0.,0.));
#1895=DIRECTION('',(1.,0.,0.));
#1896=DIRECTION('',(0.,-0.866025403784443,0.499999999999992));
#1897=AXIS2_PLACEMENT_3D('',#1894,#1895,#1896);
#1898=PLANE('',#1897);
#1899=CARTESIAN_POINT('',(0.942975,0.,0.));
#1900=DIRECTION('',(1.,0.,0.));
#1901=DIRECTION('',(0.,0.,-1.));
#1902=AXIS2_PLACEMENT_3D('',#1899,#1900,#1901);
#1903=CIRCLE('',#1902,3.52425);
#1904=EDGE_CURVE('E1307',#1852,#1881,#1903,.F.);
#1905=ORIENTED_EDGE('',*,*,#1904,.F.);
#1906=ORIENTED_EDGE('',*,*,#1853,.T.);
#1907=ORIENTED_EDGE('',*,*,#1328,.T.);
#1908=ORIENTED_EDGE('',*,*,#1888,.T.);
#1909=EDGE_LOOP('',(#1905,#1906,#1907,#1908));
#1910=FACE_BOUND('',#1909,.T.);
#1911=ADVANCED_FACE('F1141',(#1910),#1898,.T.);
#1912=CARTESIAN_POINT('',(0.942975,-2.93331751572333,-1.21501989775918));
#1913=DIRECTION('',(0.,0.500000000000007,-0.866025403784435));
#1914=DIRECTION('',(0.,0.866025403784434,0.500000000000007));
#1915=AXIS2_PLACEMENT_3D('',#1912,#1913,#1914);
#1916=PLANE('',#1915);
#1917=DIRECTION('',(0.,0.866025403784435,0.500000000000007));
#1918=VECTOR('',#1917,1.);
#1919=CARTESIAN_POINT('',(0.942975,-2.93331751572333,-1.21501989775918));
#1920=LINE('',#1919,#1918);
#1921=CARTESIAN_POINT('',(0.942975,-3.2381252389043,-1.3910007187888));
#1922=VERTEX_POINT('',#1921);
#1923=EDGE_CURVE('E732',#1922,#1303,#1920,.T.);
#1924=ORIENTED_EDGE('',*,*,#1923,.F.);
#1925=DIRECTION('',(1.,0.,0.));
#1926=VECTOR('',#1925,1.);
#1927=CARTESIAN_POINT('',(0.6858,-3.2381252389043,-1.3910007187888));
#1928=LINE('',#1927,#1926);
#1929=EDGE_CURVE('E575',#841,#1922,#1928,.T.);
#1930=ORIENTED_EDGE('',*,*,#1929,.F.);
#1931=ORIENTED_EDGE('',*,*,#842,.F.);
#1932=ORIENTED_EDGE('',*,*,#255,.T.);
#1933=ORIENTED_EDGE('',*,*,#547,.T.);
#1934=ORIENTED_EDGE('',*,*,#1310,.F.);
#1935=EDGE_LOOP('',(#1924,#1930,#1931,#1932,#1933,#1934));
#1936=FACE_BOUND('',#1935,.T.);
#1937=ADVANCED_FACE('F1137',(#1936),#1916,.F.);
#1938=CARTESIAN_POINT('',(0.942975,-3.14783743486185,-0.414420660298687));
#1939=DIRECTION('',(0.,0.,1.));
#1940=DIRECTION('',(0.,-1.,0.));
#1941=AXIS2_PLACEMENT_3D('',#1938,#1939,#1940);
#1942=PLANE('',#1941);
#1943=ORIENTED_EDGE('',*,*,#534,.T.);
#1944=ORIENTED_EDGE('',*,*,#237,.T.);
#1945=ORIENTED_EDGE('',*,*,#857,.F.);
#1946=DIRECTION('',(1.,0.,0.));
#1947=VECTOR('',#1946,1.);
#1948=CARTESIAN_POINT('',(0.6858,-3.49979907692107,-0.414420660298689));
#1949=LINE('',#1948,#1947);
#1950=CARTESIAN_POINT('',(0.942975,-3.49979907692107,-0.414420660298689));
#1951=VERTEX_POINT('',#1950);
#1952=EDGE_CURVE('E556',#850,#1951,#1949,.T.);
#1953=ORIENTED_EDGE('',*,*,#1952,.T.);
#1954=DIRECTION('',(0.,-1.,0.));
#1955=VECTOR('',#1954,1.);
#1956=CARTESIAN_POINT('',(0.942975,-3.14783743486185,-0.414420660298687));
#1957=LINE('',#1956,#1955);
#1958=EDGE_CURVE('E728',#1294,#1951,#1957,.T.);
#1959=ORIENTED_EDGE('',*,*,#1958,.F.);
#1960=ORIENTED_EDGE('',*,*,#1295,.T.);
#1961=EDGE_LOOP('',(#1943,#1944,#1945,#1953,#1959,#1960));
#1962=FACE_BOUND('',#1961,.T.);
#1963=ADVANCED_FACE('F1140',(#1962),#1942,.F.);
#1964=CARTESIAN_POINT('',(0.942975,0.,0.));
#1965=DIRECTION('',(1.,0.,0.));
#1966=DIRECTION('',(0.,-0.500000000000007,0.866025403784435));
#1967=AXIS2_PLACEMENT_3D('',#1964,#1965,#1966);
#1968=PLANE('',#1967);
#1969=CARTESIAN_POINT('',(0.942975,0.,0.));
#1970=DIRECTION('',(1.,0.,0.));
#1971=DIRECTION('',(0.,0.,-1.));
#1972=AXIS2_PLACEMENT_3D('',#1969,#1970,#1971);
#1973=CIRCLE('',#1972,3.52425);
#1974=EDGE_CURVE('E1305',#1922,#1951,#1973,.F.);
#1975=ORIENTED_EDGE('',*,*,#1974,.F.);
#1976=ORIENTED_EDGE('',*,*,#1923,.T.);
#1977=ORIENTED_EDGE('',*,*,#1304,.T.);
#1978=ORIENTED_EDGE('',*,*,#1958,.T.);
#1979=EDGE_LOOP('',(#1975,#1976,#1977,#1978));
#1980=FACE_BOUND('',#1979,.T.);
#1981=ADVANCED_FACE('F1107',(#1980),#1968,.T.);
#1982=CARTESIAN_POINT('',(0.942975,-3.14783743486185,0.414420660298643));
#1983=DIRECTION('',(0.,0.,-1.));
#1984=DIRECTION('',(0.,1.,0.));
#1985=AXIS2_PLACEMENT_3D('',#1982,#1983,#1984);
#1986=PLANE('',#1985);
#1987=DIRECTION('',(0.,1.,0.));
#1988=VECTOR('',#1987,1.);
#1989=CARTESIAN_POINT('',(0.942975,-3.14783743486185,0.414420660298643));
#1990=LINE('',#1989,#1988);
#1991=CARTESIAN_POINT('',(0.942975,-3.49979907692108,0.41442066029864));
#1992=VERTEX_POINT('',#1991);
#1993=EDGE_CURVE('E715',#1992,#1279,#1990,.T.);
#1994=ORIENTED_EDGE('',*,*,#1993,.F.);
#1995=DIRECTION('',(1.,0.,0.));
#1996=VECTOR('',#1995,1.);
#1997=CARTESIAN_POINT('',(0.6858,-3.49979907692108,0.41442066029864));
#1998=LINE('',#1997,#1996);
#1999=EDGE_CURVE('E562',#865,#1992,#1998,.T.);
#2000=ORIENTED_EDGE('',*,*,#1999,.F.);
#2001=ORIENTED_EDGE('',*,*,#866,.F.);
#2002=ORIENTED_EDGE('',*,*,#220,.T.);
#2003=ORIENTED_EDGE('',*,*,#525,.T.);
#2004=ORIENTED_EDGE('',*,*,#1286,.F.);
#2005=EDGE_LOOP('',(#1994,#2000,#2001,#2002,#2003,#2004));
#2006=FACE_BOUND('',#2005,.T.);
#2007=ADVANCED_FACE('F1103',(#2006),#1986,.F.);
#2008=CARTESIAN_POINT('',(0.942975,-2.93331751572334,1.21501989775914));
#2009=DIRECTION('',(0.,0.499999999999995,0.866025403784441));
#2010=DIRECTION('',(0.,-0.866025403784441,0.499999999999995));
#2011=AXIS2_PLACEMENT_3D('',#2008,#2009,#2010);
#2012=PLANE('',#2011);
#2013=ORIENTED_EDGE('',*,*,#512,.T.);
#2014=ORIENTED_EDGE('',*,*,#200,.T.);
#2015=ORIENTED_EDGE('',*,*,#881,.F.);
#2016=DIRECTION('',(1.,0.,0.));
#2017=VECTOR('',#2016,1.);
#2018=CARTESIAN_POINT('',(0.6858,-3.23812523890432,1.39100071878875));
#2019=LINE('',#2018,#2017);
#2020=CARTESIAN_POINT('',(0.942975,-3.23812523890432,1.39100071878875));
#2021=VERTEX_POINT('',#2020);
#2022=EDGE_CURVE('E543',#874,#2021,#2019,.T.);
#2023=ORIENTED_EDGE('',*,*,#2022,.T.);
#2024=DIRECTION('',(0.,-0.866025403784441,0.499999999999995));
#2025=VECTOR('',#2024,1.);
#2026=CARTESIAN_POINT('',(0.942975,-2.93331751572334,1.21501989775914));
#2027=LINE('',#2026,#2025);
#2028=EDGE_CURVE('E711',#1270,#2021,#2027,.T.);
#2029=ORIENTED_EDGE('',*,*,#2028,.F.);
#2030=ORIENTED_EDGE('',*,*,#1271,.T.);
#2031=EDGE_LOOP('',(#2013,#2014,#2015,#2023,#2029,#2030));
#2032=FACE_BOUND('',#2031,.T.);
#2033=ADVANCED_FACE('F1101',(#2032),#2012,.F.);
#2034=CARTESIAN_POINT('',(0.942975,0.,0.));
#2035=DIRECTION('',(1.,0.,0.));
#2036=DIRECTION('',(0.,0.,1.));
#2037=AXIS2_PLACEMENT_3D('',#2034,#2035,#2036);
#2038=PLANE('',#2037);
#2039=CARTESIAN_POINT('',(0.942975,0.,0.));
#2040=DIRECTION('',(1.,0.,0.));
#2041=DIRECTION('',(0.,0.,-1.));
#2042=AXIS2_PLACEMENT_3D('',#2039,#2040,#2041);
#2043=CIRCLE('',#2042,3.52425);
#2044=EDGE_CURVE('E1303',#1992,#2021,#2043,.F.);
#2045=ORIENTED_EDGE('',*,*,#2044,.F.);
#2046=ORIENTED_EDGE('',*,*,#1993,.T.);
#2047=ORIENTED_EDGE('',*,*,#1280,.T.);
#2048=ORIENTED_EDGE('',*,*,#2028,.T.);
#2049=EDGE_LOOP('',(#2045,#2046,#2047,#2048));
#2050=FACE_BOUND('',#2049,.T.);
#2051=ADVANCED_FACE('F1093',(#2050),#2038,.T.);
#2052=CARTESIAN_POINT('',(0.942975,-2.51889685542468,1.93281753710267));
#2053=DIRECTION('',(0.,-0.499999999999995,-0.866025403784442));
#2054=DIRECTION('',(0.,0.866025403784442,-0.499999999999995));
#2055=AXIS2_PLACEMENT_3D('',#2052,#2053,#2054);
#2056=PLANE('',#2055);
#2057=DIRECTION('',(0.,0.866025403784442,-0.499999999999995));
#2058=VECTOR('',#2057,1.);
#2059=CARTESIAN_POINT('',(0.942975,-2.51889685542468,1.93281753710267));
#2060=LINE('',#2059,#2058);
#2061=CARTESIAN_POINT('',(0.942975,-2.82370457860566,2.10879835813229));
#2062=VERTEX_POINT('',#2061);
#2063=EDGE_CURVE('E698',#2062,#1255,#2060,.T.);
#2064=ORIENTED_EDGE('',*,*,#2063,.F.);
#2065=DIRECTION('',(1.,0.,0.));
#2066=VECTOR('',#2065,1.);
#2067=CARTESIAN_POINT('',(0.6858,-2.82370457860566,2.10879835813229));
#2068=LINE('',#2067,#2066);
#2069=EDGE_CURVE('E549',#889,#2062,#2068,.T.);
#2070=ORIENTED_EDGE('',*,*,#2069,.F.);
#2071=ORIENTED_EDGE('',*,*,#890,.F.);
#2072=ORIENTED_EDGE('',*,*,#185,.T.);
#2073=ORIENTED_EDGE('',*,*,#503,.T.);
#2074=ORIENTED_EDGE('',*,*,#1262,.F.);
#2075=EDGE_LOOP('',(#2064,#2070,#2071,#2072,#2073,#2074));
#2076=FACE_BOUND('',#2075,.T.);
#2077=ADVANCED_FACE('F1089',(#2076),#2056,.F.);
#2078=CARTESIAN_POINT('',(0.942975,-1.9328175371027,2.51889685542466));
#2079=DIRECTION('',(0.,0.866025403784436,0.500000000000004));
#2080=DIRECTION('',(0.,-0.500000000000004,0.866025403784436));
#2081=AXIS2_PLACEMENT_3D('',#2078,#2079,#2080);
#2082=PLANE('',#2081);
#2083=ORIENTED_EDGE('',*,*,#490,.T.);
#2084=ORIENTED_EDGE('',*,*,#167,.T.);
#2085=ORIENTED_EDGE('',*,*,#905,.F.);
#2086=DIRECTION('',(1.,0.,0.));
#2087=VECTOR('',#2086,1.);
#2088=CARTESIAN_POINT('',(0.6858,-2.10879835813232,2.82370457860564));
#2089=LINE('',#2088,#2087);
#2090=CARTESIAN_POINT('',(0.942975,-2.10879835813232,2.82370457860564));
#2091=VERTEX_POINT('',#2090);
#2092=EDGE_CURVE('E530',#898,#2091,#2089,.T.);
#2093=ORIENTED_EDGE('',*,*,#2092,.T.);
#2094=DIRECTION('',(0.,-0.500000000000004,0.866025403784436));
#2095=VECTOR('',#2094,1.);
#2096=CARTESIAN_POINT('',(0.942975,-1.9328175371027,2.51889685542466));
#2097=LINE('',#2096,#2095);
#2098=EDGE_CURVE('E694',#1246,#2091,#2097,.T.);
#2099=ORIENTED_EDGE('',*,*,#2098,.F.);
#2100=ORIENTED_EDGE('',*,*,#1247,.T.);
#2101=EDGE_LOOP('',(#2083,#2084,#2085,#2093,#2099,#2100));
#2102=FACE_BOUND('',#2101,.T.);
#2103=ADVANCED_FACE('F1092',(#2102),#2082,.F.);
#2104=CARTESIAN_POINT('',(0.942975,0.,0.));
#2105=DIRECTION('',(1.,0.,0.));
#2106=DIRECTION('',(0.,0.499999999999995,0.866025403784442));
#2107=AXIS2_PLACEMENT_3D('',#2104,#2105,#2106);
#2108=PLANE('',#2107);
#2109=CARTESIAN_POINT('',(0.942975,0.,0.));
#2110=DIRECTION('',(1.,0.,0.));
#2111=DIRECTION('',(0.,0.,-1.));
#2112=AXIS2_PLACEMENT_3D('',#2109,#2110,#2111);
#2113=CIRCLE('',#2112,3.52425);
#2114=EDGE_CURVE('E1301',#2062,#2091,#2113,.F.);
#2115=ORIENTED_EDGE('',*,*,#2114,.F.);
#2116=ORIENTED_EDGE('',*,*,#2063,.T.);
#2117=ORIENTED_EDGE('',*,*,#1256,.T.);
#2118=ORIENTED_EDGE('',*,*,#2098,.T.);
#2119=EDGE_LOOP('',(#2115,#2116,#2117,#2118));
#2120=FACE_BOUND('',#2119,.T.);
#2121=ADVANCED_FACE('F1064',(#2120),#2108,.T.);
#2122=CARTESIAN_POINT('',(0.942975,-1.21501989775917,2.93331751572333));
#2123=DIRECTION('',(0.,-0.866025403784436,-0.500000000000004));
#2124=DIRECTION('',(0.,0.500000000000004,-0.866025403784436));
#2125=AXIS2_PLACEMENT_3D('',#2122,#2123,#2124);
#2126=PLANE('',#2125);
#2127=DIRECTION('',(0.,0.500000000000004,-0.866025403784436));
#2128=VECTOR('',#2127,1.);
#2129=CARTESIAN_POINT('',(0.942975,-1.21501989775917,2.93331751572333));
#2130=LINE('',#2129,#2128);
#2131=CARTESIAN_POINT('',(0.942975,-1.39100071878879,3.23812523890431));
#2132=VERTEX_POINT('',#2131);
#2133=EDGE_CURVE('E681',#2132,#1231,#2130,.T.);
#2134=ORIENTED_EDGE('',*,*,#2133,.F.);
#2135=DIRECTION('',(1.,0.,0.));
#2136=VECTOR('',#2135,1.);
#2137=CARTESIAN_POINT('',(0.6858,-1.39100071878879,3.23812523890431));
#2138=LINE('',#2137,#2136);
#2139=EDGE_CURVE('E536',#913,#2132,#2138,.T.);
#2140=ORIENTED_EDGE('',*,*,#2139,.F.);
#2141=ORIENTED_EDGE('',*,*,#914,.F.);
#2142=ORIENTED_EDGE('',*,*,#152,.T.);
#2143=ORIENTED_EDGE('',*,*,#481,.T.);
#2144=ORIENTED_EDGE('',*,*,#1238,.F.);
#2145=EDGE_LOOP('',(#2134,#2140,#2141,#2142,#2143,#2144));
#2146=FACE_BOUND('',#2145,.T.);
#2147=ADVANCED_FACE('F1060',(#2146),#2126,.F.);
#2148=CARTESIAN_POINT('',(0.942975,-0.414420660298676,3.14783743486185));
#2149=DIRECTION('',(0.,1.,0.));
#2150=DIRECTION('',(0.,0.,1.));
#2151=AXIS2_PLACEMENT_3D('',#2148,#2149,#2150);
#2152=PLANE('',#2151);
#2153=ORIENTED_EDGE('',*,*,#468,.T.);
#2154=ORIENTED_EDGE('',*,*,#134,.T.);
#2155=ORIENTED_EDGE('',*,*,#929,.F.);
#2156=DIRECTION('',(1.,0.,0.));
#2157=VECTOR('',#2156,1.);
#2158=CARTESIAN_POINT('',(0.6858,-0.414420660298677,3.49979907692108));
#2159=LINE('',#2158,#2157);
#2160=CARTESIAN_POINT('',(0.942975,-0.414420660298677,3.49979907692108));
#2161=VERTEX_POINT('',#2160);
#2162=EDGE_CURVE('E518',#922,#2161,#2159,.T.);
#2163=ORIENTED_EDGE('',*,*,#2162,.T.);
#2164=DIRECTION('',(0.,0.,1.));
#2165=VECTOR('',#2164,1.);
#2166=CARTESIAN_POINT('',(0.942975,-0.414420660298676,3.14783743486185));
#2167=LINE('',#2166,#2165);
#2168=EDGE_CURVE('E677',#1222,#2161,#2167,.T.);
#2169=ORIENTED_EDGE('',*,*,#2168,.F.);
#2170=ORIENTED_EDGE('',*,*,#1223,.T.);
#2171=EDGE_LOOP('',(#2153,#2154,#2155,#2163,#2169,#2170));
#2172=FACE_BOUND('',#2171,.T.);
#2173=ADVANCED_FACE('F1058',(#2172),#2152,.F.);
#2174=CARTESIAN_POINT('',(0.942975,0.,0.));
#2175=DIRECTION('',(1.,0.,0.));
#2176=DIRECTION('',(0.,0.866025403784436,0.500000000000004));
#2177=AXIS2_PLACEMENT_3D('',#2174,#2175,#2176);
#2178=PLANE('',#2177);
#2179=CARTESIAN_POINT('',(0.942975,0.,0.));
#2180=DIRECTION('',(1.,0.,0.));
#2181=DIRECTION('',(0.,0.,-1.));
#2182=AXIS2_PLACEMENT_3D('',#2179,#2180,#2181);
#2183=CIRCLE('',#2182,3.52425);
#2184=EDGE_CURVE('E1299',#2132,#2161,#2183,.F.);
#2185=ORIENTED_EDGE('',*,*,#2184,.F.);
#2186=ORIENTED_EDGE('',*,*,#2133,.T.);
#2187=ORIENTED_EDGE('',*,*,#1232,.T.);
#2188=ORIENTED_EDGE('',*,*,#2168,.T.);
#2189=EDGE_LOOP('',(#2185,#2186,#2187,#2188));
#2190=FACE_BOUND('',#2189,.T.);
#2191=ADVANCED_FACE('F1056',(#2190),#2178,.T.);
#2192=CARTESIAN_POINT('',(0.942975,0.414420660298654,3.14783743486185));
#2193=DIRECTION('',(0.,-1.,0.));
#2194=DIRECTION('',(0.,0.,-1.));
#2195=AXIS2_PLACEMENT_3D('',#2192,#2193,#2194);
#2196=PLANE('',#2195);
#2197=DIRECTION('',(0.,0.,-1.));
#2198=VECTOR('',#2197,1.);
#2199=CARTESIAN_POINT('',(0.942975,0.414420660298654,3.14783743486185));
#2200=LINE('',#2199,#2198);
#2201=CARTESIAN_POINT('',(0.942975,0.414420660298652,3.49979907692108));
#2202=VERTEX_POINT('',#2201);
#2203=EDGE_CURVE('E665',#2202,#1207,#2200,.T.);
#2204=ORIENTED_EDGE('',*,*,#2203,.F.);
#2205=DIRECTION('',(1.,0.,0.));
#2206=VECTOR('',#2205,1.);
#2207=CARTESIAN_POINT('',(0.6858,0.414420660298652,3.49979907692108));
#2208=LINE('',#2207,#2206);
#2209=EDGE_CURVE('E523',#937,#2202,#2208,.T.);
#2210=ORIENTED_EDGE('',*,*,#2209,.F.);
#2211=ORIENTED_EDGE('',*,*,#938,.F.);
#2212=ORIENTED_EDGE('',*,*,#115,.T.);
#2213=ORIENTED_EDGE('',*,*,#459,.T.);
#2214=ORIENTED_EDGE('',*,*,#1214,.F.);
#2215=EDGE_LOOP('',(#2204,#2210,#2211,#2212,#2213,#2214));
#2216=FACE_BOUND('',#2215,.T.);
#2217=ADVANCED_FACE('F1017',(#2216),#2196,.F.);
#2218=CARTESIAN_POINT('',(0.942975,1.21501989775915,2.93331751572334));
#2219=DIRECTION('',(0.,0.86602540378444,-0.499999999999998));
#2220=DIRECTION('',(0.,0.499999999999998,0.86602540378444));
#2221=AXIS2_PLACEMENT_3D('',#2218,#2219,#2220);
#2222=PLANE('',#2221);
#2223=ORIENTED_EDGE('',*,*,#441,.T.);
#2224=ORIENTED_EDGE('',*,*,#93,.T.);
#2225=ORIENTED_EDGE('',*,*,#953,.F.);
#2226=DIRECTION('',(1.,0.,0.));
#2227=VECTOR('',#2226,1.);
#2228=CARTESIAN_POINT('',(0.6858,1.39100071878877,3.23812523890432));
#2229=LINE('',#2228,#2227);
#2230=CARTESIAN_POINT('',(0.942975,1.39100071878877,3.23812523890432));
#2231=VERTEX_POINT('',#2230);
#2232=EDGE_CURVE('E497',#946,#2231,#2229,.T.);
#2233=ORIENTED_EDGE('',*,*,#2232,.T.);
#2234=DIRECTION('',(0.,0.499999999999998,0.86602540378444));
#2235=VECTOR('',#2234,1.);
#2236=CARTESIAN_POINT('',(0.942975,1.21501989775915,2.93331751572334));
#2237=LINE('',#2236,#2235);
#2238=EDGE_CURVE('E661',#1198,#2231,#2237,.T.);
#2239=ORIENTED_EDGE('',*,*,#2238,.F.);
#2240=ORIENTED_EDGE('',*,*,#1199,.T.);
#2241=EDGE_LOOP('',(#2223,#2224,#2225,#2233,#2239,#2240));
#2242=FACE_BOUND('',#2241,.T.);
#2243=ADVANCED_FACE('F1024',(#2242),#2222,.F.);
#2244=CARTESIAN_POINT('',(0.942975,0.,0.));
#2245=DIRECTION('',(1.,0.,0.));
#2246=DIRECTION('',(0.,1.,0.));
#2247=AXIS2_PLACEMENT_3D('',#2244,#2245,#2246);
#2248=PLANE('',#2247);
#2249=CARTESIAN_POINT('',(0.942975,0.,0.));
#2250=DIRECTION('',(1.,0.,0.));
#2251=DIRECTION('',(0.,0.,-1.));
#2252=AXIS2_PLACEMENT_3D('',#2249,#2250,#2251);
#2253=CIRCLE('',#2252,3.52425);
#2254=EDGE_CURVE('E1297',#2202,#2231,#2253,.F.);
#2255=ORIENTED_EDGE('',*,*,#2254,.F.);
#2256=ORIENTED_EDGE('',*,*,#2203,.T.);
#2257=ORIENTED_EDGE('',*,*,#1208,.T.);
#2258=ORIENTED_EDGE('',*,*,#2238,.T.);
#2259=EDGE_LOOP('',(#2255,#2256,#2257,#2258));
#2260=FACE_BOUND('',#2259,.T.);
#2261=ADVANCED_FACE('F1053',(#2260),#2248,.T.);
#2262=CARTESIAN_POINT('',(0.942975,1.93281753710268,2.51889685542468));
#2263=DIRECTION('',(0.,-0.86602540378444,0.499999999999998));
#2264=DIRECTION('',(0.,-0.499999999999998,-0.86602540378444));
#2265=AXIS2_PLACEMENT_3D('',#2262,#2263,#2264);
#2266=PLANE('',#2265);
#2267=DIRECTION('',(0.,-0.499999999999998,-0.86602540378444));
#2268=VECTOR('',#2267,1.);
#2269=CARTESIAN_POINT('',(0.942975,1.93281753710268,2.51889685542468));
#2270=LINE('',#2269,#2268);
#2271=CARTESIAN_POINT('',(0.942975,2.1087983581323,2.82370457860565));
#2272=VERTEX_POINT('',#2271);
#2273=EDGE_CURVE('E502',#2272,#1183,#2270,.T.);
#2274=ORIENTED_EDGE('',*,*,#2273,.F.);
#2275=DIRECTION('',(1.,0.,0.));
#2276=VECTOR('',#2275,1.);
#2277=CARTESIAN_POINT('',(0.6858,2.1087983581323,2.82370457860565));
#2278=LINE('',#2277,#2276);
#2279=EDGE_CURVE('E500',#961,#2272,#2278,.T.);
#2280=ORIENTED_EDGE('',*,*,#2279,.F.);
#2281=ORIENTED_EDGE('',*,*,#962,.F.);
#2282=ORIENTED_EDGE('',*,*,#78,.T.);
#2283=ORIENTED_EDGE('',*,*,#432,.T.);
#2284=ORIENTED_EDGE('',*,*,#1190,.F.);
#2285=EDGE_LOOP('',(#2274,#2280,#2281,#2282,#2283,#2284));
#2286=FACE_BOUND('',#2285,.T.);
#2287=ADVANCED_FACE('F501',(#2286),#2266,.F.);
#2288=CARTESIAN_POINT('',(0.942975,2.51889685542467,1.93281753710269));
#2289=DIRECTION('',(0.,0.500000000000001,-0.866025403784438));
#2290=DIRECTION('',(0.,0.866025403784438,0.500000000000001));
#2291=AXIS2_PLACEMENT_3D('',#2288,#2289,#2290);
#2292=PLANE('',#2291);
#2293=ORIENTED_EDGE('',*,*,#662,.T.);
#2294=ORIENTED_EDGE('',*,*,#44,.T.);
#2295=ORIENTED_EDGE('',*,*,#977,.F.);
#2296=DIRECTION('',(1.,0.,0.));
#2297=VECTOR('',#2296,1.);
#2298=CARTESIAN_POINT('',(0.6858,2.82370457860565,2.10879835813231));
#2299=LINE('',#2298,#2297);
#2300=CARTESIAN_POINT('',(0.942975,2.82370457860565,2.10879835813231));
#2301=VERTEX_POINT('',#2300);
#2302=EDGE_CURVE('E505',#970,#2301,#2299,.T.);
#2303=ORIENTED_EDGE('',*,*,#2302,.T.);
#2304=DIRECTION('',(0.,0.866025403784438,0.500000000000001));
#2305=VECTOR('',#2304,1.);
#2306=CARTESIAN_POINT('',(0.942975,2.51889685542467,1.93281753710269));
#2307=LINE('',#2306,#2305);
#2308=EDGE_CURVE('E646',#1174,#2301,#2307,.T.);
#2309=ORIENTED_EDGE('',*,*,#2308,.F.);
#2310=ORIENTED_EDGE('',*,*,#1175,.T.);
#2311=EDGE_LOOP('',(#2293,#2294,#2295,#2303,#2309,#2310));
#2312=FACE_BOUND('',#2311,.T.);
#2313=ADVANCED_FACE('F1373',(#2312),#2292,.F.);
#2314=CARTESIAN_POINT('',(0.942975,0.,0.));
#2315=DIRECTION('',(1.,0.,0.));
#2316=DIRECTION('',(0.,0.86602540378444,-0.499999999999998));
#2317=AXIS2_PLACEMENT_3D('',#2314,#2315,#2316);
#2318=PLANE('',#2317);
#2319=CARTESIAN_POINT('',(0.942975,0.,0.));
#2320=DIRECTION('',(1.,0.,0.));
#2321=DIRECTION('',(0.,0.,-1.));
#2322=AXIS2_PLACEMENT_3D('',#2319,#2320,#2321);
#2323=CIRCLE('',#2322,3.52425);
#2324=EDGE_CURVE('E1289',#2272,#2301,#2323,.F.);
#2325=ORIENTED_EDGE('',*,*,#2324,.F.);
#2326=ORIENTED_EDGE('',*,*,#2273,.T.);
#2327=ORIENTED_EDGE('',*,*,#1184,.T.);
#2328=ORIENTED_EDGE('',*,*,#2308,.T.);
#2329=EDGE_LOOP('',(#2325,#2326,#2327,#2328));
#2330=FACE_BOUND('',#2329,.T.);
#2331=ADVANCED_FACE('F1374',(#2330),#2318,.T.);
#2332=CARTESIAN_POINT('',(0.6858,0.,0.));
#2333=DIRECTION('',(1.,0.,0.));
#2334=DIRECTION('',(0.,0.,-1.));
#2335=AXIS2_PLACEMENT_3D('',#2332,#2333,#2334);
#2336=CYLINDRICAL_SURFACE('',#2335,3.52425);
#2337=ORIENTED_EDGE('',*,*,#1624,.T.);
#2338=ORIENTED_EDGE('',*,*,#1602,.F.);
#2339=ORIENTED_EDGE('',*,*,#995,.F.);
#2340=ORIENTED_EDGE('',*,*,#1579,.T.);
#2341=EDGE_LOOP('',(#2337,#2338,#2339,#2340));
#2342=FACE_BOUND('',#2341,.T.);
#2343=ADVANCED_FACE('F1521',(#2342),#2336,.T.);
#2344=CARTESIAN_POINT('',(0.6858,0.,0.));
#2345=DIRECTION('',(1.,0.,0.));
#2346=DIRECTION('',(0.,0.,-1.));
#2347=AXIS2_PLACEMENT_3D('',#2344,#2345,#2346);
#2348=CYLINDRICAL_SURFACE('',#2347,3.52425);
#2349=ORIENTED_EDGE('',*,*,#2324,.T.);
#2350=ORIENTED_EDGE('',*,*,#2302,.F.);
#2351=ORIENTED_EDGE('',*,*,#971,.F.);
#2352=ORIENTED_EDGE('',*,*,#2279,.T.);
#2353=EDGE_LOOP('',(#2349,#2350,#2351,#2352));
#2354=FACE_BOUND('',#2353,.T.);
#2355=ADVANCED_FACE('F508',(#2354),#2348,.T.);
#2356=CARTESIAN_POINT('',(0.6858,0.,0.));
#2357=DIRECTION('',(1.,0.,0.));
#2358=DIRECTION('',(0.,0.,-1.));
#2359=AXIS2_PLACEMENT_3D('',#2356,#2357,#2358);
#2360=CYLINDRICAL_SURFACE('',#2359,3.52425);
#2361=ORIENTED_EDGE('',*,*,#2254,.T.);
#2362=ORIENTED_EDGE('',*,*,#2232,.F.);
#2363=ORIENTED_EDGE('',*,*,#947,.F.);
#2364=ORIENTED_EDGE('',*,*,#2209,.T.);
#2365=EDGE_LOOP('',(#2361,#2362,#2363,#2364));
#2366=FACE_BOUND('',#2365,.T.);
#2367=ADVANCED_FACE('F1021',(#2366),#2360,.T.);
#2368=CARTESIAN_POINT('',(0.6858,0.,0.));
#2369=DIRECTION('',(1.,0.,0.));
#2370=DIRECTION('',(0.,0.,-1.));
#2371=AXIS2_PLACEMENT_3D('',#2368,#2369,#2370);
#2372=CYLINDRICAL_SURFACE('',#2371,3.52425);
#2373=ORIENTED_EDGE('',*,*,#2184,.T.);
#2374=ORIENTED_EDGE('',*,*,#2162,.F.);
#2375=ORIENTED_EDGE('',*,*,#923,.F.);
#2376=ORIENTED_EDGE('',*,*,#2139,.T.);
#2377=EDGE_LOOP('',(#2373,#2374,#2375,#2376));
#2378=FACE_BOUND('',#2377,.T.);
#2379=ADVANCED_FACE('F1492',(#2378),#2372,.T.);
#2380=CARTESIAN_POINT('',(0.6858,0.,0.));
#2381=DIRECTION('',(1.,0.,0.));
#2382=DIRECTION('',(0.,0.,-1.));
#2383=AXIS2_PLACEMENT_3D('',#2380,#2381,#2382);
#2384=CYLINDRICAL_SURFACE('',#2383,3.52425);
#2385=ORIENTED_EDGE('',*,*,#2114,.T.);
#2386=ORIENTED_EDGE('',*,*,#2092,.F.);
#2387=ORIENTED_EDGE('',*,*,#899,.F.);
#2388=ORIENTED_EDGE('',*,*,#2069,.T.);
#2389=EDGE_LOOP('',(#2385,#2386,#2387,#2388));
#2390=FACE_BOUND('',#2389,.T.);
#2391=ADVANCED_FACE('F1494',(#2390),#2384,.T.);
#2392=CARTESIAN_POINT('',(0.6858,0.,0.));
#2393=DIRECTION('',(1.,0.,0.));
#2394=DIRECTION('',(0.,0.,-1.));
#2395=AXIS2_PLACEMENT_3D('',#2392,#2393,#2394);
#2396=CYLINDRICAL_SURFACE('',#2395,3.52425);
#2397=ORIENTED_EDGE('',*,*,#2044,.T.);
#2398=ORIENTED_EDGE('',*,*,#2022,.F.);
#2399=ORIENTED_EDGE('',*,*,#875,.F.);
#2400=ORIENTED_EDGE('',*,*,#1999,.T.);
#2401=EDGE_LOOP('',(#2397,#2398,#2399,#2400));
#2402=FACE_BOUND('',#2401,.T.);
#2403=ADVANCED_FACE('F1500',(#2402),#2396,.T.);
#2404=CARTESIAN_POINT('',(0.6858,0.,0.));
#2405=DIRECTION('',(1.,0.,0.));
#2406=DIRECTION('',(0.,0.,-1.));
#2407=AXIS2_PLACEMENT_3D('',#2404,#2405,#2406);
#2408=CYLINDRICAL_SURFACE('',#2407,3.52425);
#2409=ORIENTED_EDGE('',*,*,#1974,.T.);
#2410=ORIENTED_EDGE('',*,*,#1952,.F.);
#2411=ORIENTED_EDGE('',*,*,#851,.F.);
#2412=ORIENTED_EDGE('',*,*,#1929,.T.);
#2413=EDGE_LOOP('',(#2409,#2410,#2411,#2412));
#2414=FACE_BOUND('',#2413,.T.);
#2415=ADVANCED_FACE('F1507',(#2414),#2408,.T.);
#2416=CARTESIAN_POINT('',(0.6858,0.,0.));
#2417=DIRECTION('',(1.,0.,0.));
#2418=DIRECTION('',(0.,0.,-1.));
#2419=AXIS2_PLACEMENT_3D('',#2416,#2417,#2418);
#2420=CYLINDRICAL_SURFACE('',#2419,3.52425);
#2421=ORIENTED_EDGE('',*,*,#1904,.T.);
#2422=ORIENTED_EDGE('',*,*,#1882,.F.);
#2423=ORIENTED_EDGE('',*,*,#827,.F.);
#2424=ORIENTED_EDGE('',*,*,#1859,.T.);
#2425=EDGE_LOOP('',(#2421,#2422,#2423,#2424));
#2426=FACE_BOUND('',#2425,.T.);
#2427=ADVANCED_FACE('F1510',(#2426),#2420,.T.);
#2428=CARTESIAN_POINT('',(0.6858,0.,0.));
#2429=DIRECTION('',(1.,0.,0.));
#2430=DIRECTION('',(0.,0.,-1.));
#2431=AXIS2_PLACEMENT_3D('',#2428,#2429,#2430);
#2432=CYLINDRICAL_SURFACE('',#2431,3.52425);
#2433=ORIENTED_EDGE('',*,*,#1834,.T.);
#2434=ORIENTED_EDGE('',*,*,#1812,.F.);
#2435=ORIENTED_EDGE('',*,*,#803,.F.);
#2436=ORIENTED_EDGE('',*,*,#1789,.T.);
#2437=EDGE_LOOP('',(#2433,#2434,#2435,#2436));
#2438=FACE_BOUND('',#2437,.T.);
#2439=ADVANCED_FACE('F1431',(#2438),#2432,.T.);
#2440=CARTESIAN_POINT('',(0.6858,0.,0.));
#2441=DIRECTION('',(1.,0.,0.));
#2442=DIRECTION('',(0.,0.,-1.));
#2443=AXIS2_PLACEMENT_3D('',#2440,#2441,#2442);
#2444=CYLINDRICAL_SURFACE('',#2443,3.52425);
#2445=ORIENTED_EDGE('',*,*,#1764,.T.);
#2446=ORIENTED_EDGE('',*,*,#1742,.F.);
#2447=ORIENTED_EDGE('',*,*,#779,.F.);
#2448=ORIENTED_EDGE('',*,*,#1719,.T.);
#2449=EDGE_LOOP('',(#2445,#2446,#2447,#2448));
#2450=FACE_BOUND('',#2449,.T.);
#2451=ADVANCED_FACE('F1312',(#2450),#2444,.T.);
#2452=CARTESIAN_POINT('',(0.6858,0.,0.));
#2453=DIRECTION('',(1.,0.,0.));
#2454=DIRECTION('',(0.,0.,-1.));
#2455=AXIS2_PLACEMENT_3D('',#2452,#2453,#2454);
#2456=CYLINDRICAL_SURFACE('',#2455,3.52425);
#2457=ORIENTED_EDGE('',*,*,#1694,.T.);
#2458=ORIENTED_EDGE('',*,*,#1672,.F.);
#2459=ORIENTED_EDGE('',*,*,#1048,.F.);
#2460=ORIENTED_EDGE('',*,*,#1649,.T.);
#2461=EDGE_LOOP('',(#2457,#2458,#2459,#2460));
#2462=FACE_BOUND('',#2461,.T.);
#2463=ADVANCED_FACE('F1518',(#2462),#2456,.T.);
#2464=CLOSED_SHELL('',(#66,#99,#140,#173,#206,#243,#276,#309,#346,#379,#420,#452,#474,#496,#518,
#540,#562,#584,#606,#628,#655,#677,#694,#714,#734,#754,#1058,#1081,#1103,#1410,#1430,#1450,
#1470,#1479,#1505,#1531,#1549,#1561,#1587,#1613,#1631,#1657,#1683,#1701,#1727,#1753,#1771,#1797,
#1823,#1841,#1867,#1893,#1911,#1937,#1963,#1981,#2007,#2033,#2051,#2077,#2103,#2121,#2147,#2173,
#2191,#2217,#2243,#2261,#2287,#2313,#2331,#2343,#2355,#2367,#2379,#2391,#2403,#2415,#2427,#2439,
#2451,#2463));
#2465=MANIFOLD_SOLID_BREP('B2',#2464);
#2466=ADVANCED_BREP_SHAPE_REPRESENTATION('',(#18,#2465),#14);
#2467=SHAPE_DEFINITION_REPRESENTATION(#9,#2466);
ENDSEC;
END-ISO-10303-21;
